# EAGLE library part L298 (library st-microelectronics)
DUAL FULL-BRIDGE DRIVER

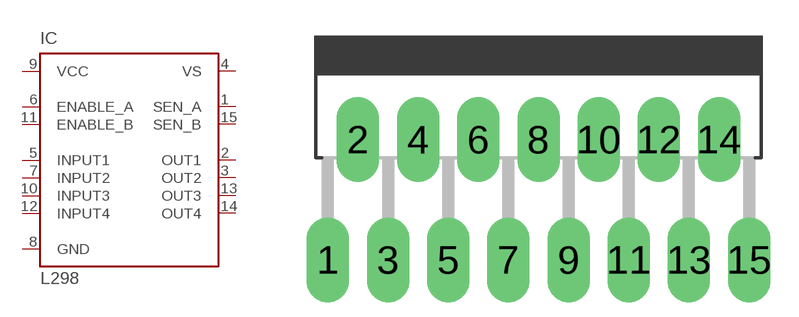
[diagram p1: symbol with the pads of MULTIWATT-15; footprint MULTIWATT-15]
Designator prefix IC

## L298 (MPN: L298N; OC_FARNELL: 1589425; OC_NEWARK: 32M1527)  [MULTIWATT-15]
1  SEN_A  in
2  OUT1  out
3  OUT2  out
4  VS  pwr
5  INPUT1  in
6  ENABLE_A  in
7  INPUT2  in
8  GND  pwr
9  VCC  pwr
10  INPUT3  in
11  ENABLE_B  in
12  INPUT4  in
13  OUT3  out
14  OUT4  out
15  SEN_B  in

## Footprint MULTIWATT-15 (pad centres in mm)
Multiwatt 15 lead
drill 1.2 long: 1 -8.89,-7.62; 2 -7.62,-2.54; 3 -6.35,-7.62; 4 -5.08,-2.54; 5 -3.81,-7.62; 6 -2.54,-2.54; 7 -1.27,-7.62; 8 0,-2.54; 9 1.27,-7.62; 10 2.54,-2.54; 11 3.81,-7.62; 12 5.08,-2.54; 13 6.35,-7.62; 14 7.62,-2.54; 15 8.89,-7.62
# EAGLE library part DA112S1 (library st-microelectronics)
DIODE ARRAY (ASD)

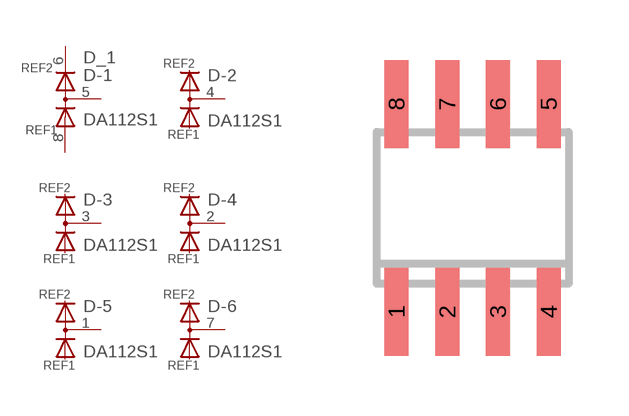
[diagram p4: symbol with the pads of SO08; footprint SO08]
Designator prefix D; gates _1=REF -1=D-1 -2=D-2-1 -3=D-2-1 -4=D-2-1 -5=D-2-1 -6=D-2-1

## DA112S1 (MF: Arrow Electronics; MPN: DA112S1; OC_FARNELL: 9802223; OC_NEWARK: 89K0514)  [SO08]
1  -5:K  pas
2  -4:K  pas
3  -3:K  pas
4  -2:K  pas
5  -1:K  pas
6  _1:REF2  pas
7  -6:K  pas
8  _1:REF1  pas

## Footprint SO08 (pad centres in mm)
SMALL OUTLINE INTEGRATED CIRCUIT body 3.9 mm/JEDEC MS-012AA
smd 0.6 x 2.2: 1 -1.905,-2.6; 2 -0.635,-2.6; 3 0.635,-2.6; 4 1.905,-2.6; 5 1.905,2.6; 6 0.635,2.6; 7 -0.635,2.6; 8 -1.905,2.6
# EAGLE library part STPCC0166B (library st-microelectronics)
MICROCONTROLLER

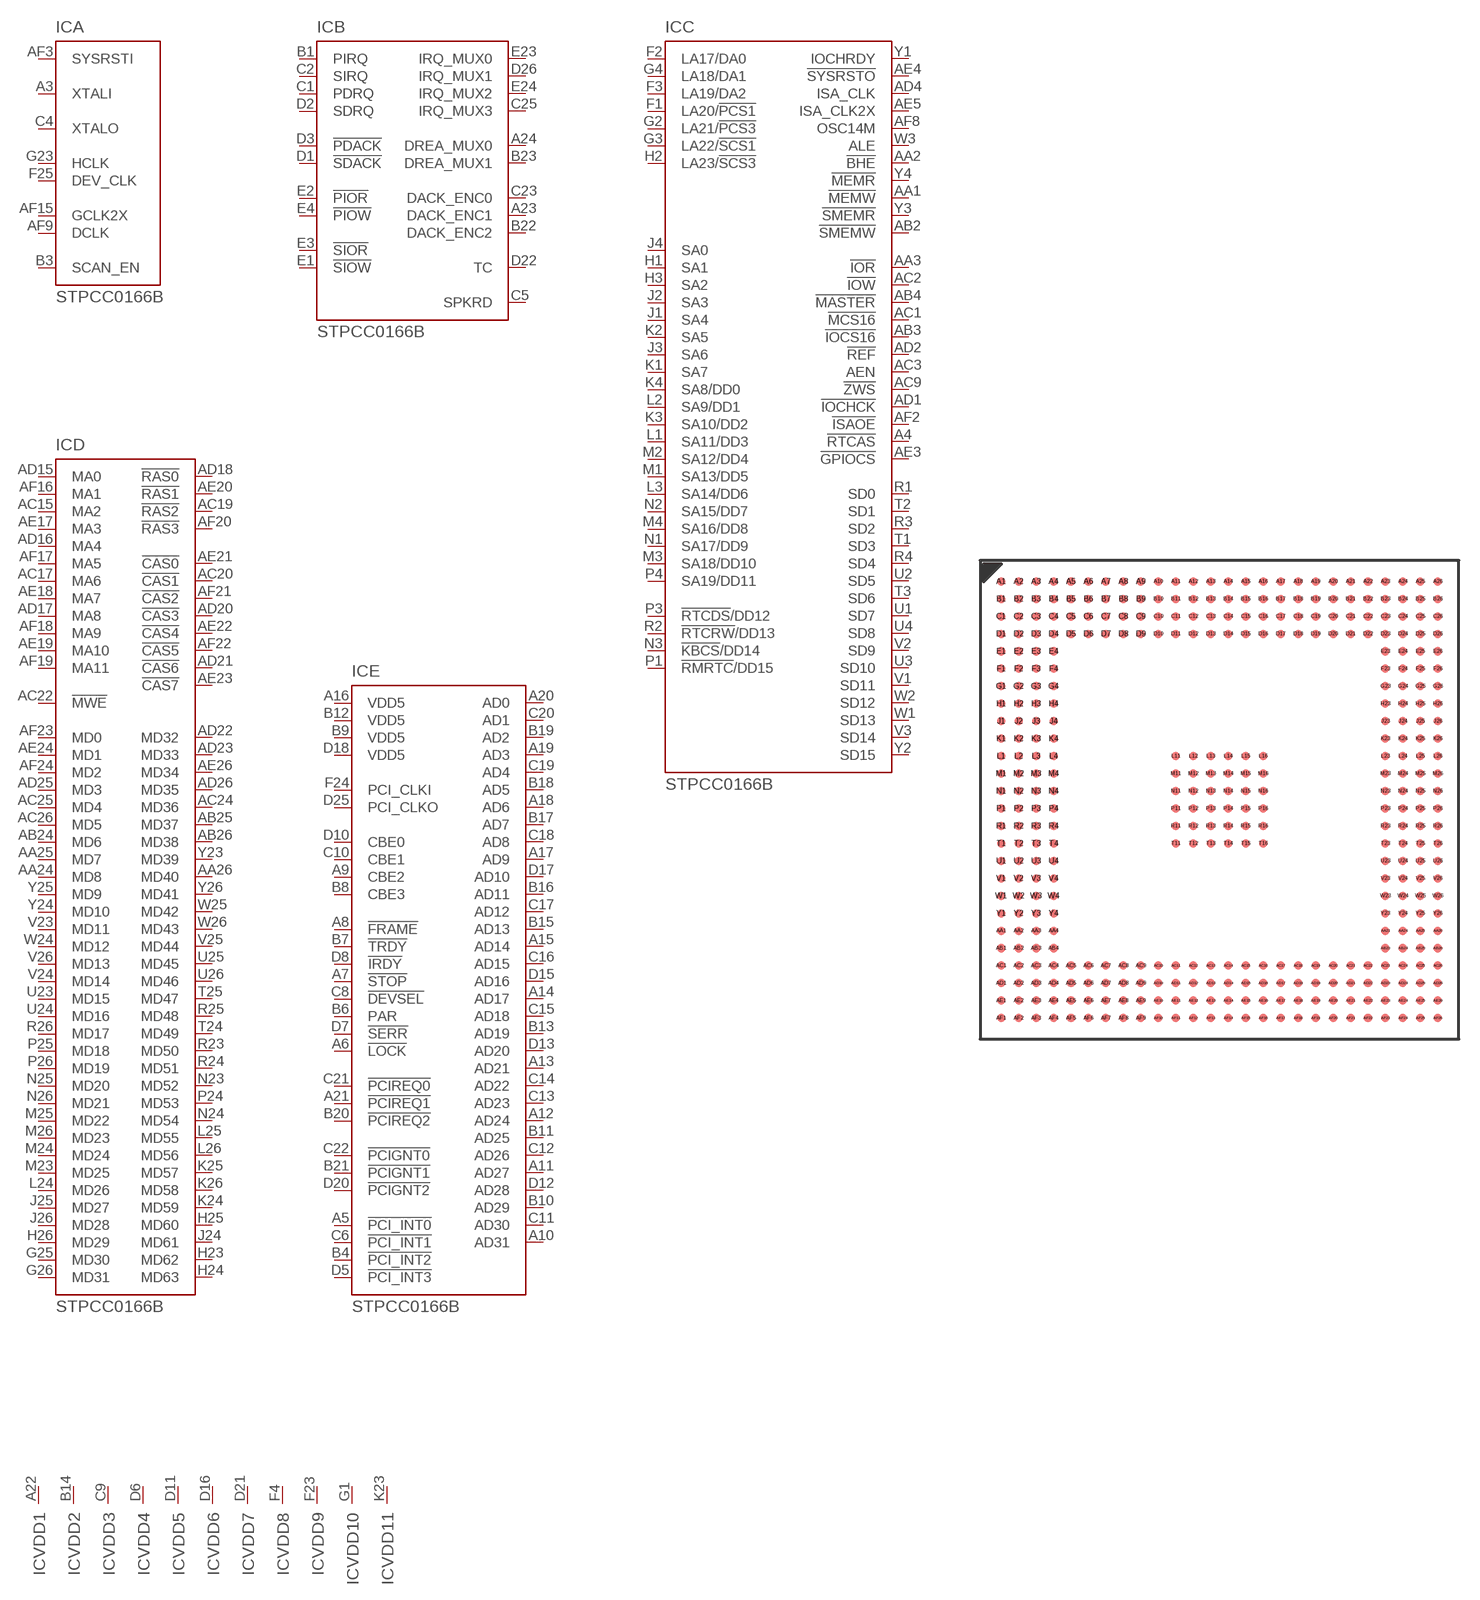
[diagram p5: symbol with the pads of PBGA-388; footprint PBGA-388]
Designator prefix IC; gates A=C0166BAS B=C0166IDE C=C0166ISA D=C0166MEM E=C0166PCI VDD1=VDD VDD2=VDD VDD3=VDD VDD4=VDD VDD5=VDD VDD6=VDD VDD7=VDD VDD8=VDD VDD9=VDD VDD10=VDD VDD11=VDD VDD12=VDD VDD13=VDD VDD14=VDD VDD15=VDD VDD16=VDD VDD17=VDD VDD18=VDD VDD19=VDD VDD20=VDD VDD21=VDD VDD22=VDD VDD23=VDD VDD24=VDD VSS1=VSS VSS2=VSS VSS3=VSS VSS4=VSS VSS5=VSS VSS6=VSS VSS7=VSS VSS8=VSS VSS9=VSS VSS10=VSS VSS11=VSS VSS12=VSS VSS13=VSS VSS14=VSS VSS15=VSS VSS16=VSS VSS17=VSS VSS18=VSS VSS19=VSS VSS20=VSS VSS21=VSS VSS22=VSS VSS23=VSS VSS24=VSS VDD25=VDD VDD26=VDD VSS25=VSS VSS26=VSS VSS27=VSS VSS28=VSS VSS29=VSS VSS30=VSS VSS31=VSS VSS32=VSS VSS33=VSS VSS34=VSS VSS35=VSS VSS36=VSS VSS37=VSS VSS38=VSS VSS39=VSS VSS40=VSS VSS41=VSS VSS42=VSS VSS43=VSS VSS44=VSS VSS45=VSS VSS46=VSS VSS47=VSS VSS48=VSS VSS49=VSS VSS50=VSS VSS51=VSS VSS52=VSS VSS53=VSS VSS54=VSS VSS55=VSS VSS56=VSS VSS57=VSS VSS58=VSS VSS59=VSS VSS60=VSS VSS61=VSS VSS62=VSS VSS63=VSS VSS64=VSS VSS65=VSS VSS66=VSS VSS67=VSS VSS68=VSS RESERV1=RESERVED RESERV2=RESERVED RESERV3=RESERVED RESERV4=RESERVED F=C0166MON VSS69=VSS

## STPCC0166B (MPN: STPCC5HEBC; OC_FARNELL: unknown; OC_NEWARK: 37M6674)  [PBGA-388]
A1  VSS1:VSS  pwr
A2  VSS69:VSS  pwr
A3  A:XTALI  in
A4  C:!RTCAS  out
A5  E:!PCI_INT0  in
A6  E:!LOCK  in
A7  E:!STOP
A8  E:!FRAME
A9  E:CBE2
A10  E:AD31
A11  E:AD27
A12  E:AD24
A13  E:AD21
A14  E:AD17
A15  E:AD14
A16  E:VDD5  pwr
A17  E:AD9
A18  E:AD6
A19  E:AD3
A20  E:AD0
A21  E:!PCIREQ1  in
A22  VDD1:VDD  pwr
A23  B:DACK_ENC1  out
A24  B:DREA_MUX0  in
A25  RESERV4:RESERVED  nc
A26  VSS2:VSS  pwr
AA1  C:!MEMW
AA2  C:!BHE
AA3  C:!IOR
AA4  VDD19:VDD  pwr
AA23  VDD20:VDD  pwr
AA24  D:MD8
AA25  D:MD7
AA26  D:MD40
AB1  VDD21:VDD  pwr
AB2  C:!SMEMW  out
AB3  C:!IOCS16  in
AB4  C:!MASTER  in
AB23  VDD22:VDD  pwr
AB24  D:MD6
AB25  D:MD37
AB26  D:MD38
AC1  C:!MCS16  in
AC2  C:!IOW
AC3  C:AEN  out
AC4  VSS55:VSS  pwr
AC5  F:HSYNC  out
AC6  VDD23:VDD  pwr
AC7  F:VDD_DAC1  in
AC8  VSS56:VSS  pwr
AC9  C:!ZWS  in
AC10  F:GREEN_TV  out
AC11  VDD24:VDD  pwr
AC12  F:VCLK  in
AC13  VSS57:VSS  pwr
AC14  F:VIN4  in
AC15  D:MA2
AC16  VDD25:VDD  pwr
AC17  D:MA6
AC18  VSS58:VSS  pwr
AC19  D:!RAS2  out
AC20  D:!CAS1  out
AC21  VDD26:VDD  pwr
AC22  D:!MWE
AC23  VSS59:VSS  pwr
AC24  D:MD36
AC25  D:MD4
AC26  D:MD5
AD1  C:!IOCHCK  in
AD2  C:!REF  out
AD3  VSS60:VSS  pwr
AD4  C:ISA_CLK  out
AD5  F:VSYNC  out
AD6  F:GREEN  out
AD7  F:VREF_DAC  in
AD8  F:IREF1_TV  in
AD9  F:ODD_EVEN  out
AD10  F:VREF2_TV  in
AD11  F:CVBS  out
AD12  F:VIN2  in
AD13  F:VIN6  in
AD14  F:VIN1  in
AD15  D:MA0
AD16  D:MA4
AD17  D:MA8
AD18  D:!RAS0  out
AD19  F:VDDGCKPLL  in
AD20  D:!CAS3  out
AD21  D:!CAS6  out
AD22  D:MD32
AD23  D:MD33
AD24  VSS61:VSS  pwr
AD25  D:MD3
AD26  D:MD35
AE1  VSS62:VSS  pwr
AE2  VSS63:VSS  pwr
AE3  C:!GPIOCS
AE4  C:!SYSRSTO  out
AE5  C:ISA_CLK2X  out
AE6  F:RED  out
AE7  F:VSS_DAC1  in
AE8  F:RSET  in
AE9  F:VREF1_TV  in
AE10  F:VCS  out
AE11  F:IREF2_TV  in
AE12  F:VSSA_TV  in
AE13  F:VIN0  in
AE14  F:VIN3  in
AE15  F:VIN7  in
AE16  VSS64:VSS  pwr
AE17  D:MA3
AE18  D:MA7
AE19  D:MA10
AE20  D:!RAS1  out
AE21  D:!CAS0  out
AE22  D:!CAS4  out
AE23  D:!CAS7  out
AE24  D:MD1
AE25  VSS65:VSS  pwr
AE26  D:MD34
AF1  VSS66:VSS  pwr
AF2  C:!ISAOE  out
AF3  A:SYSRSTI  in
AF4  F:VDD_DAC2  in
AF5  F:COMP  in
AF6  F:BLUE  out
AF7  F:VSS_DAC2  in
AF8  C:OSC14M  out
AF9  A:DCLK
AF10  F:RED_TV  out
AF11  F:BLUE_TV  out
AF12  F:VDDA_TV  in
AF13  F:VDDDCKPLL  in
AF14  F:VIN5  in
AF15  A:GCLK2X
AF16  D:MA1
AF17  D:MA5
AF18  D:MA9
AF19  D:MA11
AF20  D:!RAS3  out
AF21  D:!CAS2  out
AF22  D:!CAS5  out
AF23  D:MD0
AF24  D:MD2
AF25  VSS67:VSS  pwr
AF26  VSS68:VSS  pwr
B1  B:PIRQ  in
B2  VSS3:VSS  pwr
B3  A:SCAN_EN  in
B4  E:!PCI_INT2  in
B5  F:SLC/DDC1
B6  E:PAR
B7  E:!TRDY
B8  E:CBE3
B9  E:VDD5  pwr
B10  E:AD29
B11  E:AD25
B12  E:VDD5  pwr
B13  E:AD19
B14  VDD2:VDD  pwr
B15  E:AD13
B16  E:AD11
B17  E:AD7
B18  E:AD5
B19  E:AD2
B20  E:!PCIREQ2  in
B21  E:!PCIGNT1  out
B22  B:DACK_ENC2  out
B23  B:DREA_MUX1  in
B24  RESERV3:RESERVED  nc
B25  VSS4:VSS  pwr
B26  VSS5:VSS  pwr
C1  B:PDRQ  in
C2  B:SIRQ  in
C3  VSS6:VSS  pwr
C4  A:XTALO
C5  B:SPKRD  out
C6  E:!PCI_INT1  in
C7  F:SDA/DDC0
C8  E:!DEVSEL
C9  VDD3:VDD  pwr
C10  E:CBE1
C11  E:AD30
C12  E:AD26
C13  E:AD23
C14  E:AD22
C15  E:AD18
C16  E:AD15
C17  E:AD12
C18  E:AD8
C19  E:AD4
C20  E:AD1
C21  E:!PCIREQ0  in
C22  E:!PCIGNT0  out
C23  B:DACK_ENC0  out
C24  VSS7:VSS  pwr
C25  B:IRQ_MUX3  in
C26  RESERV1:RESERVED  nc
D1  B:!SDACK  out
D2  B:SDRQ  in
D3  B:!PDACK  out
D4  VSS8:VSS  pwr
D5  E:!PCI_INT3  in
D6  VDD4:VDD  pwr
D7  E:!SERR  out
D8  E:!IRDY
D9  VSS9:VSS  pwr
D10  E:CBE0
D11  VDD5:VDD  pwr
D12  E:AD28
D13  E:AD20
D14  VSS10:VSS  pwr
D15  E:AD16
D16  VDD6:VDD  pwr
D17  E:AD10
D18  E:VDD5  pwr
D19  VSS11:VSS  pwr
D20  E:!PCIGNT2  out
D21  VDD7:VDD  pwr
D22  B:TC  out
D23  VSS12:VSS  pwr
D24  RESERV2:RESERVED  nc
D25  E:PCI_CLKO  out
D26  B:IRQ_MUX1  in
E1  B:!SIOW  out
E2  B:!PIOR
E3  B:!SIOR
E4  B:!PIOW  out
E23  B:IRQ_MUX0  in
E24  B:IRQ_MUX2  in
E25  F:VSS_DLL1  in
E26  F:VSS_DLL2  in
F1  C:LA20/!PCS1
F2  C:LA17/DA0  out
F3  C:LA19/DA2  out
F4  VDD8:VDD  pwr
F23  VDD9:VDD  pwr
F24  E:PCI_CLKI  in
F25  A:DEV_CLK  out
F26  F:VDDHCKPLL  in
G1  VDD10:VDD  pwr
G2  C:LA21/!PCS3
G3  C:LA22/!SCS1
G4  C:LA18/DA1  out
G23  A:HCLK  out
G24  F:VDDDEVPLL  in
G25  D:MD30
G26  D:MD31
H1  C:SA1
H2  C:LA23/!SCS3
H3  C:SA2
H4  VSS13:VSS  pwr
H23  D:MD62
H24  D:MD63
H25  D:MD60
H26  D:MD29
J1  C:SA4
J2  C:SA3
J3  C:SA6
J4  C:SA0
J23  VSS14:VSS  pwr
J24  D:MD61
J25  D:MD27
J26  D:MD28
K1  C:SA7
K2  C:SA5
K3  C:SA10/DD2
K4  C:SA8/DD0
K23  VDD11:VDD  pwr
K24  D:MD59
K25  D:MD57
K26  D:MD58
L1  C:SA11/DD3
L2  C:SA9/DD1
L3  C:SA14/DD6
L4  VDD12:VDD  pwr
L11  VSS15:VSS  pwr
L12  VSS16:VSS  pwr
L13  VSS17:VSS  pwr
L14  VSS18:VSS  pwr
L15  VSS19:VSS  pwr
L16  VSS20:VSS  pwr
L23  VDD13:VDD  pwr
L24  D:MD26
L25  D:MD55
L26  D:MD56
M1  C:SA13/DD5
M2  C:SA12/DD4
M3  C:SA18/DD10
M4  C:SA16/DD8
M11  VSS21:VSS  pwr
M12  VSS22:VSS  pwr
M13  VSS23:VSS  pwr
M14  VSS24:VSS  pwr
M15  VSS25:VSS  pwr
M16  VSS26:VSS  pwr
M23  D:MD25
M24  D:MD24
M25  D:MD22
M26  D:MD23
N1  C:SA17/DD9
N2  C:SA15/DD7
N3  C:!KBCS!/DD14
N4  VSS27:VSS  pwr
N11  VSS28:VSS  pwr
N12  VSS29:VSS  pwr
N13  VSS30:VSS  pwr
N14  VSS31:VSS  pwr
N15  VSS32:VSS  pwr
N16  VSS33:VSS  pwr
N23  D:MD52
N24  D:MD54
N25  D:MD20
N26  D:MD21
P1  C:!RMRTC!/DD15
P2  VDD14:VDD  pwr
P3  C:!RTCDS!/DD12
P4  C:SA19/DD11
P11  VSS34:VSS  pwr
P12  VSS35:VSS  pwr
P13  VSS36:VSS  pwr
P14  VSS37:VSS  pwr
P15  VSS38:VSS  pwr
P16  VSS39:VSS  pwr
P23  VSS40:VSS  pwr
P24  D:MD53
P25  D:MD18
P26  D:MD19
R1  C:SD0
R2  C:!RTCRW!/DD13
R3  C:SD2
R4  C:SD4
R11  VSS41:VSS  pwr
R12  VSS42:VSS  pwr
R13  VSS43:VSS  pwr
R14  VSS44:VSS  pwr
R15  VSS45:VSS  pwr
R16  VSS46:VSS  pwr
R23  D:MD50
R24  D:MD51
R25  D:MD48
R26  D:MD17
T1  C:SD3
T2  C:SD1
T3  C:SD6
T4  VDD15:VDD  pwr
T11  VSS47:VSS  pwr
T12  VSS48:VSS  pwr
T13  VSS49:VSS  pwr
T14  VSS50:VSS  pwr
T15  VSS51:VSS  pwr
T16  VSS52:VSS  pwr
T23  VDD16:VDD  pwr
T24  D:MD49
T25  D:MD47
T26  VDD17:VDD  pwr
U1  C:SD7
U2  C:SD5
U3  C:SD10
U4  C:SD8
U23  D:MD15
U24  D:MD16
U25  D:MD45
U26  D:MD46
V1  C:SD11
V2  C:SD9
V3  C:SD14
V4  VSS53:VSS  pwr
V23  D:MD11
V24  D:MD14
V25  D:MD44
V26  D:MD13
W1  C:SD13
W2  C:SD12
W3  C:ALE  out
W4  VDD18:VDD  pwr
W23  VSS54:VSS  pwr
W24  D:MD12
W25  D:MD42
W26  D:MD43
Y1  C:IOCHRDY
Y2  C:SD15
Y3  C:!SMEMR  out
Y4  C:!MEMR
Y23  D:MD39
Y24  D:MD10
Y25  D:MD9
Y26  D:MD41

## Footprint PBGA-388 (pad centres in mm)
Plastic Ball Grid Array
smd 0.635 x 0.635: A1 -15.875,15.875; A2 -14.605,15.875; A3 -13.335,15.875; A4 -12.065,15.875; A5 -10.795,15.875; A6 -9.525,15.875; A7 -8.255,15.875; A8 -6.985,15.875; A9 -5.715,15.875; A10 -4.445,15.875; A11 -3.175,15.875; A12 -1.905,15.875; A13 -0.635,15.875; A14 0.635,15.875; A15 1.905,15.875; A16 3.175,15.875; A17 4.445,15.875; A18 5.715,15.875; A19 6.985,15.875; A20 8.255,15.875; A21 9.525,15.875; A22 10.795,15.875; A23 12.065,15.875; A24 13.335,15.875; A25 14.605,15.875; A26 15.875,15.875; AA1 -15.875,-9.525; AA2 -14.605,-9.525; AA3 -13.335,-9.525; AA4 -12.065,-9.525; AA23 12.065,-9.525; AA24 13.335,-9.525; AA25 14.605,-9.525; AA26 15.875,-9.525; AB1 -15.875,-10.795; AB2 -14.605,-10.795; AB3 -13.335,-10.795; AB4 -12.065,-10.795; AB23 12.065,-10.795; AB24 13.335,-10.795; AB25 14.605,-10.795; AB26 15.875,-10.795; AC1 -15.875,-12.065; AC2 -14.605,-12.065; AC3 -13.335,-12.065; AC4 -12.065,-12.065; AC5 -10.795,-12.065; AC6 -9.525,-12.065; AC7 -8.255,-12.065; AC8 -6.985,-12.065; AC9 -5.715,-12.065; AC10 -4.445,-12.065; AC11 -3.175,-12.065; AC12 -1.905,-12.065; AC13 -0.635,-12.065; AC14 0.635,-12.065; AC15 1.905,-12.065; AC16 3.175,-12.065; AC17 4.445,-12.065; AC18 5.715,-12.065; AC19 6.985,-12.065; AC20 8.255,-12.065; AC21 9.525,-12.065; AC22 10.795,-12.065; AC23 12.065,-12.065; AC24 13.335,-12.065; AC25 14.605,-12.065; AC26 15.875,-12.065; AD1 -15.875,-13.335; AD2 -14.605,-13.335; AD3 -13.335,-13.335; AD4 -12.065,-13.335; AD5 -10.795,-13.335; AD6 -9.525,-13.335; AD7 -8.255,-13.335; AD8 -6.985,-13.335; AD9 -5.715,-13.335; AD10 -4.445,-13.335; AD11 -3.175,-13.335; AD12 -1.905,-13.335; AD13 -0.635,-13.335; AD14 0.635,-13.335; AD15 1.905,-13.335; AD16 3.175,-13.335; AD17 4.445,-13.335; AD18 5.715,-13.335; AD19 6.985,-13.335; AD20 8.255,-13.335; AD21 9.525,-13.335; AD22 10.795,-13.335; AD23 12.065,-13.335; AD24 13.335,-13.335; AD25 14.605,-13.335; AD26 15.875,-13.335; AE1 -15.875,-14.605; AE2 -14.605,-14.605; AE3 -13.335,-14.605; AE4 -12.065,-14.605; AE5 -10.795,-14.605; AE6 -9.525,-14.605; AE7 -8.255,-14.605; AE8 -6.985,-14.605; AE9 -5.715,-14.605; AE10 -4.445,-14.605; AE11 -3.175,-14.605; AE12 -1.905,-14.605; AE13 -0.635,-14.605; AE14 0.635,-14.605; AE15 1.905,-14.605; AE16 3.175,-14.605; AE17 4.445,-14.605; AE18 5.715,-14.605; AE19 6.985,-14.605; AE20 8.255,-14.605; AE21 9.525,-14.605; AE22 10.795,-14.605; AE23 12.065,-14.605; AE24 13.335,-14.605; AE25 14.605,-14.605; AE26 15.875,-14.605; AF1 -15.875,-15.875; AF2 -14.605,-15.875; AF3 -13.335,-15.875; AF4 -12.065,-15.875; AF5 -10.795,-15.875; AF6 -9.525,-15.875; AF7 -8.255,-15.875; AF8 -6.985,-15.875; AF9 -5.715,-15.875; AF10 -4.445,-15.875; AF11 -3.175,-15.875; AF12 -1.905,-15.875; AF13 -0.635,-15.875; AF14 0.635,-15.875; AF15 1.905,-15.875; AF16 3.175,-15.875; AF17 4.445,-15.875; AF18 5.715,-15.875; AF19 6.985,-15.875; AF20 8.255,-15.875; AF21 9.525,-15.875; AF22 10.795,-15.875; AF23 12.065,-15.875; AF24 13.335,-15.875; AF25 14.605,-15.875; AF26 15.875,-15.875; B1 -15.875,14.605; B2 -14.605,14.605; B3 -13.335,14.605; B4 -12.065,14.605; B5 -10.795,14.605; B6 -9.525,14.605; B7 -8.255,14.605; B8 -6.985,14.605; B9 -5.715,14.605; B10 -4.445,14.605; B11 -3.175,14.605; B12 -1.905,14.605; B13 -0.635,14.605; B14 0.635,14.605; B15 1.905,14.605; B16 3.175,14.605; B17 4.445,14.605; B18 5.715,14.605; B19 6.985,14.605; B20 8.255,14.605; B21 9.525,14.605; B22 10.795,14.605; B23 12.065,14.605; B24 13.335,14.605; B25 14.605,14.605; B26 15.875,14.605; C1 -15.875,13.335; C2 -14.605,13.335; C3 -13.335,13.335; C4 -12.065,13.335; C5 -10.795,13.335; C6 -9.525,13.335; C7 -8.255,13.335; C8 -6.985,13.335; C9 -5.715,13.335; C10 -4.445,13.335; C11 -3.175,13.335; C12 -1.905,13.335; C13 -0.635,13.335; C14 0.635,13.335; C15 1.905,13.335; C16 3.175,13.335; C17 4.445,13.335; C18 5.715,13.335; C19 6.985,13.335; C20 8.255,13.335; C21 9.525,13.335; C22 10.795,13.335; C23 12.065,13.335; C24 13.335,13.335; C25 14.605,13.335; C26 15.875,13.335; D1 -15.875,12.065; D2 -14.605,12.065; D3 -13.335,12.065; D4 -12.065,12.065; D5 -10.795,12.065; D6 -9.525,12.065; D7 -8.255,12.065; D8 -6.985,12.065; D9 -5.715,12.065; D10 -4.445,12.065; D11 -3.175,12.065; D12 -1.905,12.065; D13 -0.635,12.065; D14 0.635,12.065; D15 1.905,12.065; D16 3.175,12.065; D17 4.445,12.065; D18 5.715,12.065; D19 6.985,12.065; D20 8.255,12.065; D21 9.525,12.065; D22 10.795,12.065; D23 12.065,12.065; D24 13.335,12.065; D25 14.605,12.065; D26 15.875,12.065; E1 -15.875,10.795; E2 -14.605,10.795; E3 -13.335,10.795; E4 -12.065,10.795; E23 12.065,10.795; E24 13.335,10.795; E25 14.605,10.795; E26 15.875,10.795; F1 -15.875,9.525; F2 -14.605,9.525; F3 -13.335,9.525; F4 -12.065,9.525; F23 12.065,9.525; F24 13.335,9.525; F25 14.605,9.525; F26 15.875,9.525; G1 -15.875,8.255; G2 -14.605,8.255; G3 -13.335,8.255; G4 -12.065,8.255; G23 12.065,8.255; G24 13.335,8.255; G25 14.605,8.255; G26 15.875,8.255; H1 -15.875,6.985; H2 -14.605,6.985; H3 -13.335,6.985; H4 -12.065,6.985; H23 12.065,6.985; H24 13.335,6.985; H25 14.605,6.985; H26 15.875,6.985; J1 -15.875,5.715; J2 -14.605,5.715; J3 -13.335,5.715; J4 -12.065,5.715; J23 12.065,5.715; J24 13.335,5.715; J25 14.605,5.715; J26 15.875,5.715; K1 -15.875,4.445; K2 -14.605,4.445; K3 -13.335,4.445; K4 -12.065,4.445; K23 12.065,4.445; K24 13.335,4.445; K25 14.605,4.445; K26 15.875,4.445; L1 -15.875,3.175; L2 -14.605,3.175; L3 -13.335,3.175; L4 -12.065,3.175; L11 -3.175,3.175; L12 -1.905,3.175; L13 -0.635,3.175; L14 0.635,3.175; L15 1.905,3.175; L16 3.175,3.175; L23 12.065,3.175; L24 13.335,3.175; L25 14.605,3.175; L26 15.875,3.175; M1 -15.875,1.905; M2 -14.605,1.905; M3 -13.335,1.905; M4 -12.065,1.905; M11 -3.175,1.905; M12 -1.905,1.905; M13 -0.635,1.905; M14 0.635,1.905; M15 1.905,1.905; M16 3.175,1.905; M23 12.065,1.905; M24 13.335,1.905; M25 14.605,1.905; M26 15.875,1.905; N1 -15.875,0.635; N2 -14.605,0.635; N3 -13.335,0.635; N4 -12.065,0.635; N11 -3.175,0.635; N12 -1.905,0.635; N13 -0.635,0.635; N14 0.635,0.635; N15 1.905,0.635; N16 3.175,0.635; N23 12.065,0.635; N24 13.335,0.635; N25 14.605,0.635; N26 15.875,0.635; P1 -15.875,-0.635; P2 -14.605,-0.635; P3 -13.335,-0.635; P4 -12.065,-0.635; P11 -3.175,-0.635; P12 -1.905,-0.635; P13 -0.635,-0.635; P14 0.635,-0.635; P15 1.905,-0.635; P16 3.175,-0.635; P23 12.065,-0.635; P24 13.335,-0.635; P25 14.605,-0.635; P26 15.875,-0.635; R1 -15.875,-1.905; R2 -14.605,-1.905; R3 -13.335,-1.905; R4 -12.065,-1.905; R11 -3.175,-1.905; R12 -1.905,-1.905; R13 -0.635,-1.905; R14 0.635,-1.905; R15 1.905,-1.905; R16 3.175,-1.905; R23 12.065,-1.905; R24 13.335,-1.905; R25 14.605,-1.905; R26 15.875,-1.905; T1 -15.875,-3.175; T2 -14.605,-3.175; T3 -13.335,-3.175; T4 -12.065,-3.175; T11 -3.175,-3.175; T12 -1.905,-3.175; T13 -0.635,-3.175; T14 0.635,-3.175; T15 1.905,-3.175; T16 3.175,-3.175; T23 12.065,-3.175; T24 13.335,-3.175; T25 14.605,-3.175; T26 15.875,-3.175; U1 -15.875,-4.445; U2 -14.605,-4.445; U3 -13.335,-4.445; U4 -12.065,-4.445; U23 12.065,-4.445; U24 13.335,-4.445; U25 14.605,-4.445; U26 15.875,-4.445; V1 -15.875,-5.715; V2 -14.605,-5.715; V3 -13.335,-5.715; V4 -12.065,-5.715; V23 12.065,-5.715; V24 13.335,-5.715; V25 14.605,-5.715; V26 15.875,-5.715; W1 -15.875,-6.985; W2 -14.605,-6.985; W3 -13.335,-6.985; W4 -12.065,-6.985; W23 12.065,-6.985; W24 13.335,-6.985; W25 14.605,-6.985; W26 15.875,-6.985; Y1 -15.875,-8.255; Y2 -14.605,-8.255; Y3 -13.335,-8.255; Y4 -12.065,-8.255; Y23 12.065,-8.255; Y24 13.335,-8.255; Y25 14.605,-8.255; Y26 15.875,-8.255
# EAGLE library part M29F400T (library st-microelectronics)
FLASH MEMORY 512 KB x 8 or 256 KB x 16, boot block

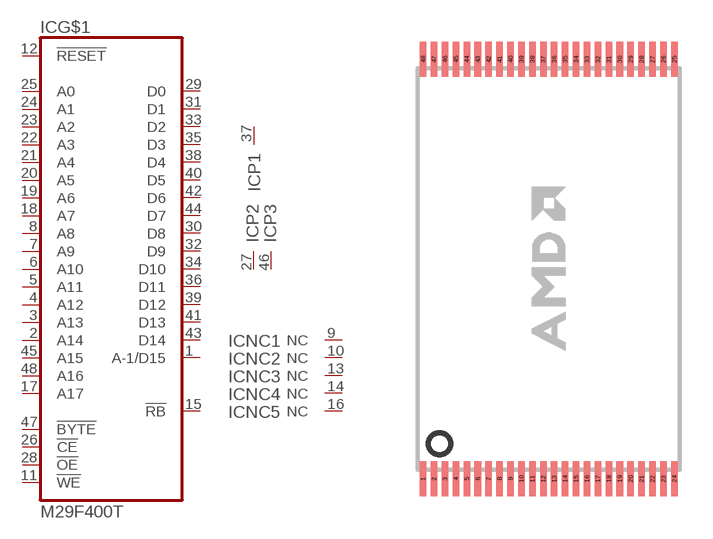
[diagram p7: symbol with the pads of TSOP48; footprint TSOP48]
Designator prefix IC; gates G$1=M29F400 P1=VCC P2=GND P3=GND NC1=NC NC2=NC NC3=NC NC4=NC NC5=NC

## M29F400T (MPN: MBM29F400TC-70PFTN-SFLE1; OC_FARNELL: 1201518; OC_NEWARK: 89M1908)  [TSOP48]
1  G$1:A-1/D15  hiz
2  G$1:A14  in
3  G$1:A13  in
4  G$1:A12  in
5  G$1:A11  in
6  G$1:A10  in
7  G$1:A9  in
8  G$1:A8  in
9  NC1:NC  nc
10  NC2:NC  nc
11  G$1:!WE  in
12  G$1:!RESET  in
13  NC3:NC  nc
14  NC4:NC  nc
15  G$1:!RB  out
16  NC5:NC  nc
17  G$1:A17  in
18  G$1:A7  in
19  G$1:A6  in
20  G$1:A5  in
21  G$1:A4  in
22  G$1:A3  in
23  G$1:A2  in
24  G$1:A1  in
25  G$1:A0  in
26  G$1:!CE  in
27  P2:GND  pwr
28  G$1:!OE  in
29  G$1:D0  hiz
30  G$1:D8  hiz
31  G$1:D1  hiz
32  G$1:D9  hiz
33  G$1:D2  hiz
34  G$1:D10  hiz
35  G$1:D3  hiz
36  G$1:D11  hiz
37  P1:VCC  pwr
38  G$1:D4  hiz
39  G$1:D12  hiz
40  G$1:D5  hiz
41  G$1:D13  hiz
42  G$1:D6  hiz
43  G$1:D14  hiz
44  G$1:D7  hiz
45  G$1:A15  in
46  P3:GND  pwr
47  G$1:!BYTE  in
48  G$1:A16  in

## Footprint TSOP48 (pad centres in mm)
Thin Small Outline Plastic Package
smd 0.3 x 1.6: 1 -5.75,-9.6; 2 -5.25,-9.6; 3 -4.75,-9.6; 4 -4.25,-9.6; 5 -3.75,-9.6; 6 -3.25,-9.6; 7 -2.75,-9.6; 8 -2.25,-9.6; 9 -1.75,-9.6; 10 -1.25,-9.6; 11 -0.75,-9.6; 12 -0.25,-9.6; 13 0.25,-9.6; 14 0.75,-9.6; 15 1.25,-9.6; 16 1.75,-9.6; 17 2.25,-9.6; 18 2.75,-9.6; 19 3.25,-9.6; 20 3.75,-9.6; 21 4.25,-9.6; 22 4.75,-9.6; 23 5.25,-9.6; 24 5.75,-9.6; 25 5.75,9.6; 26 5.25,9.6; 27 4.75,9.6; 28 4.25,9.6; 29 3.75,9.6; 30 3.25,9.6; 31 2.75,9.6; 32 2.25,9.6; 33 1.75,9.6; 34 1.25,9.6; 35 0.75,9.6; 36 0.25,9.6; 37 -0.25,9.6; 38 -0.75,9.6; 39 -1.25,9.6; 40 -1.75,9.6; 41 -2.25,9.6; 42 -2.75,9.6; 43 -3.25,9.6; 44 -3.75,9.6; 45 -4.25,9.6; 46 -4.75,9.6; 47 -5.25,9.6; 48 -5.75,9.6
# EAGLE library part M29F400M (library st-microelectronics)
FLASH MEMORY 512 KB x 8 or 256 KB x 16, boot block

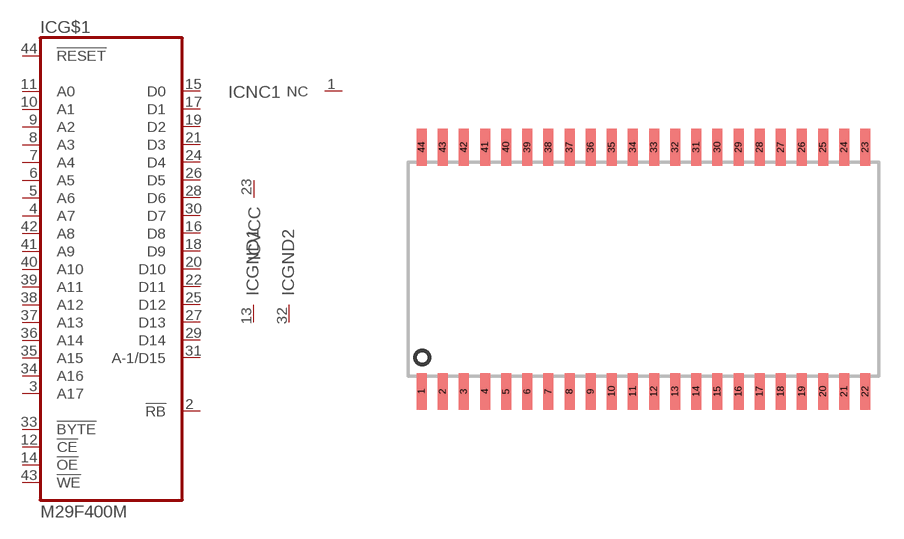
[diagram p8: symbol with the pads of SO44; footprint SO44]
Designator prefix IC; gates G$1=M29F400 NC1=NC VCC=VCC GND1=GND GND2=GND

## M29F400M (MF: SPANSION LLC; MPN: AM29F400BB-90SF; OC_FARNELL: 1607577; OC_NEWARK: 58K5516)  [SO44]
1  NC1:NC  nc
2  G$1:!RB  out
3  G$1:A17  in
4  G$1:A7  in
5  G$1:A6  in
6  G$1:A5  in
7  G$1:A4  in
8  G$1:A3  in
9  G$1:A2  in
10  G$1:A1  in
11  G$1:A0  in
12  G$1:!CE  in
13  GND1:GND  pwr
14  G$1:!OE  in
15  G$1:D0  hiz
16  G$1:D8  hiz
17  G$1:D1  hiz
18  G$1:D9  hiz
19  G$1:D2  hiz
20  G$1:D10  hiz
21  G$1:D3  hiz
22  G$1:D11  hiz
23  VCC:VCC  pwr
24  G$1:D4  hiz
25  G$1:D12  hiz
26  G$1:D5  hiz
27  G$1:D13  hiz
28  G$1:D6  hiz
29  G$1:D14  hiz
30  G$1:D7  hiz
31  G$1:A-1/D15  hiz
32  GND2:GND  pwr
33  G$1:!BYTE  in
34  G$1:A16  in
35  G$1:A15  in
36  G$1:A14  in
37  G$1:A13  in
38  G$1:A12  in
39  G$1:A11  in
40  G$1:A10  in
41  G$1:A9  in
42  G$1:A8  in
43  G$1:!WE  in
44  G$1:!RESET  in

## Footprint SO44 (pad centres in mm)
Small Outline Package
smd 0.6 x 2.2: 1 -13.335,-7.34; 2 -12.065,-7.34; 3 -10.795,-7.34; 4 -9.525,-7.34; 5 -8.255,-7.34; 6 -6.985,-7.34; 7 -5.715,-7.34; 8 -4.445,-7.34; 9 -3.175,-7.34; 10 -1.905,-7.34; 11 -0.635,-7.34; 12 0.635,-7.34; 13 1.905,-7.34; 14 3.175,-7.34; 15 4.445,-7.34; 16 5.715,-7.34; 17 6.985,-7.34; 18 8.255,-7.34; 19 9.525,-7.34; 20 10.795,-7.34; 21 12.065,-7.34; 22 13.335,-7.34; 23 13.335,7.34; 24 12.065,7.34; 25 10.795,7.34; 26 9.525,7.34; 27 8.255,7.34; 28 6.985,7.34; 29 5.715,7.34; 30 4.445,7.34; 31 3.175,7.34; 32 1.905,7.34; 33 0.635,7.34; 34 -0.635,7.34; 35 -1.905,7.34; 36 -3.175,7.34; 37 -4.445,7.34; 38 -5.715,7.34; 39 -6.985,7.34; 40 -8.255,7.34; 41 -9.525,7.34; 42 -10.795,7.34; 43 -12.065,7.34; 44 -13.335,7.34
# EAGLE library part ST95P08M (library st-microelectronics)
Serial EEPROM SPI bus, 1 K x 8

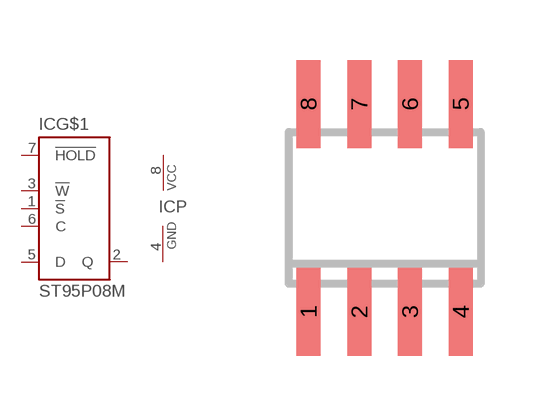
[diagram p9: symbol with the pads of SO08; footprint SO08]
Designator prefix IC; gates G$1=ST95P08 P=PWRN

## ST95P08M (OC_FARNELL: unknown; OC_NEWARK: unknown)  [SO08]
1  G$1:!S  in
2  G$1:Q  hiz
3  G$1:!W  in
4  P:GND  pwr
5  G$1:D  in
6  G$1:C  in
7  G$1:!HOLD  in
8  P:VCC  pwr

## Footprint SO08 (pad centres in mm)
SMALL OUTLINE INTEGRATED CIRCUIT body 3.9 mm/JEDEC MS-012AA
smd 0.6 x 2.2: 1 -1.905,-2.6; 2 -0.635,-2.6; 3 0.635,-2.6; 4 1.905,-2.6; 5 1.905,2.6; 6 0.635,2.6; 7 -0.635,2.6; 8 -1.905,2.6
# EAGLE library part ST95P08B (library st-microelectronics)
Serial EEPROM SPI bus, 1 K x 8

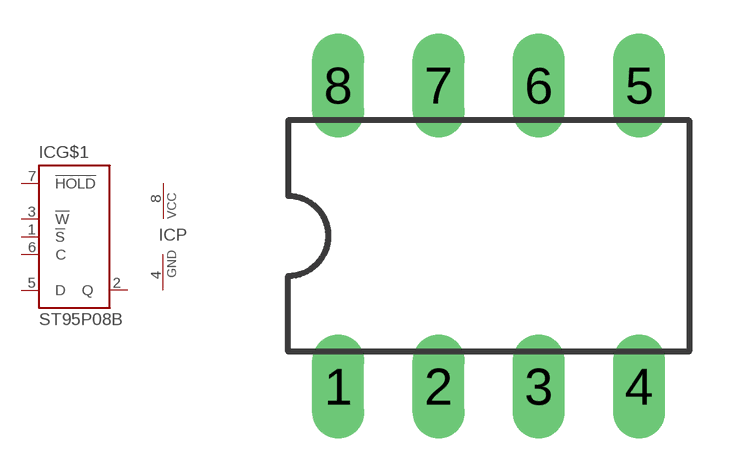
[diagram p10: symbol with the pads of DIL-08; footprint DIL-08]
Designator prefix IC; gates G$1=ST95P08 P=PWRN

## ST95P08B (OC_FARNELL: unknown; OC_NEWARK: unknown)  [DIL-08]
1  G$1:!S  in
2  G$1:Q  hiz
3  G$1:!W  in
4  P:GND  pwr
5  G$1:D  in
6  G$1:C  in
7  G$1:!HOLD  in
8  P:VCC  pwr

## Footprint DIL-08 (pad centres in mm)
Dual In Line Package
drill 0.813 long: 1 -3.81,-3.81; 2 -1.27,-3.81; 3 1.27,-3.81; 4 3.81,-3.81; 5 3.81,3.81; 6 1.27,3.81; 7 -1.27,3.81; 8 -3.81,3.81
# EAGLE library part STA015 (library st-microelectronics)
MP3 AUDIO DECODER with ADPCM capability

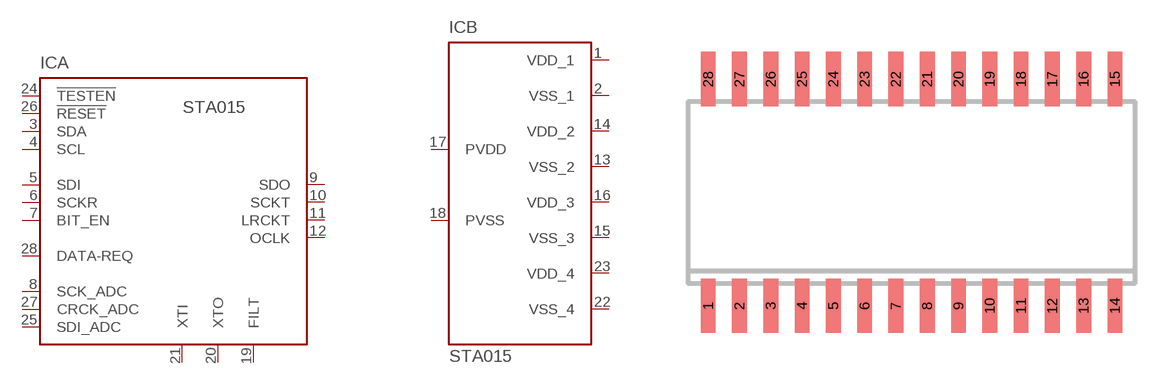
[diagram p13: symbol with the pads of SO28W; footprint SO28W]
Designator prefix IC; gates A=STA015S B=STA015PW

## STA015 (MPN: STA015$; OC_FARNELL: unknown; OC_NEWARK: 37M6100)  [SO28W]
1  B:VDD_1  pwr
2  B:VSS_1  pwr
3  A:SDA
4  A:SCL  in
5  A:SDI  in
6  A:SCKR  in
7  A:BIT_EN  in
8  A:SCK_ADC  in
9  A:SDO  out
10  A:SCKT  out
11  A:LRCKT  out
12  A:OCLK
13  B:VSS_2  pwr
14  B:VDD_2  pwr
15  B:VSS_3  pwr
16  B:VDD_3  pwr
17  B:PVDD  pwr
18  B:PVSS  pwr
19  A:FILT  out
20  A:XTO  out
21  A:XTI  in
22  B:VSS_4  pwr
23  B:VDD_4  pwr
24  A:!TESTEN  in
25  A:SDI_ADC  in
26  A:!RESET  in
27  A:CRCK_ADC  in
28  A:DATA-REQ  out

## Footprint SO28W (pad centres in mm)
SMALL OUTLINE INTEGRATED CIRCUIT wide body 7.5 mm/JEDEC MO-119AB
smd 0.6 x 2.2: 1 -8.255,-4.6; 2 -6.985,-4.6; 3 -5.715,-4.6; 4 -4.445,-4.6; 5 -3.175,-4.6; 6 -1.905,-4.6; 7 -0.635,-4.6; 8 0.635,-4.6; 9 1.905,-4.6; 10 3.175,-4.6; 11 4.445,-4.6; 12 5.715,-4.6; 13 6.985,-4.6; 14 8.255,-4.6; 15 8.255,4.6; 16 6.985,4.6; 17 5.715,4.6; 18 4.445,4.6; 19 3.175,4.6; 20 1.905,4.6; 21 0.635,4.6; 22 -0.635,4.6; 23 -1.905,4.6; 24 -3.175,4.6; 25 -4.445,4.6; 26 -5.715,4.6; 27 -6.985,4.6; 28 -8.255,4.6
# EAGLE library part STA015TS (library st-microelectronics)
MP3 AUDIO DECODER with ADPCM capability

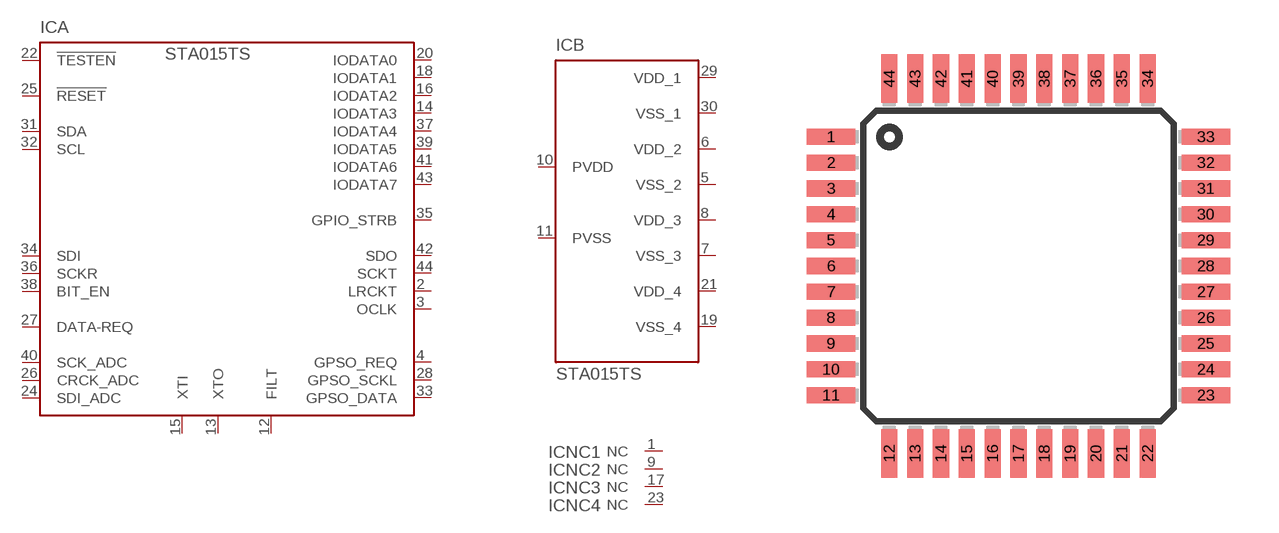
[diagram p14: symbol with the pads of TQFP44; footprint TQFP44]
Designator prefix IC; gates A=STA015TS B=STA015PW NC1=NC NC2=NC NC3=NC NC4=NC

## STA015TS (MPN: STA015T$; OC_FARNELL: unknown; OC_NEWARK: 37M6104)  [TQFP44]
1  NC1:NC  nc
2  A:LRCKT  out
3  A:OCLK
4  A:GPSO_REQ  out
5  B:VSS_2  pwr
6  B:VDD_2  pwr
7  B:VSS_3  pwr
8  B:VDD_3  pwr
9  NC2:NC  nc
10  B:PVDD  pwr
11  B:PVSS  pwr
12  A:FILT  out
13  A:XTO  out
14  A:IODATA3
15  A:XTI  in
16  A:IODATA2
17  NC3:NC  nc
18  A:IODATA1
19  B:VSS_4  pwr
20  A:IODATA0
21  B:VDD_4  pwr
22  A:!TESTEN  in
23  NC4:NC  nc
24  A:SDI_ADC  in
25  A:!RESET  in
26  A:CRCK_ADC  in
27  A:DATA-REQ  out
28  A:GPSO_SCKL  out
29  B:VDD_1  pwr
30  B:VSS_1  pwr
31  A:SDA
32  A:SCL  in
33  A:GPSO_DATA  out
34  A:SDI  in
35  A:GPIO_STRB
36  A:SCKR  in
37  A:IODATA4
38  A:BIT_EN  in
39  A:IODATA5
40  A:SCK_ADC  in
41  A:IODATA6
42  A:SDO  out
43  A:IODATA7
44  A:SCKT  out

## Footprint TQFP44 (pad centres in mm)
Thin Quad Flat Pack package type TQ
smd 1.5 x 0.5: 1 -5.8,4; 2 -5.8,3.2; 3 -5.8,2.4; 4 -5.8,1.6; 5 -5.8,0.8; 6 -5.8,0; 7 -5.8,-0.8; 8 -5.8,-1.6; 9 -5.8,-2.4; 10 -5.8,-3.2; 11 -5.8,-4; 23 5.8,-4; 24 5.8,-3.2; 25 5.8,-2.4; 26 5.8,-1.6; 27 5.8,-0.8; 28 5.8,0; 29 5.8,0.8; 30 5.8,1.6; 31 5.8,2.4; 32 5.8,3.2; 33 5.8,4
smd 0.5 x 1.5: 12 -4,-5.8; 13 -3.2,-5.8; 14 -2.4,-5.8; 15 -1.6,-5.8; 16 -0.8,-5.8; 17 0,-5.8; 18 0.8,-5.8; 19 1.6,-5.8; 20 2.4,-5.8; 21 3.2,-5.8; 22 4,-5.8; 34 4,5.8; 35 3.2,5.8; 36 2.4,5.8; 37 1.6,5.8; 38 0.8,5.8; 39 0,5.8; 40 -0.8,5.8; 41 -1.6,5.8; 42 -2.4,5.8; 43 -3.2,5.8; 44 -4,5.8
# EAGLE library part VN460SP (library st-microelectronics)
SINGLE CHANNEL HIGH SIDE SMART POWER SOLID STATE RELAY http://eu.st.com/stonline/ 3732.pdf and 5691.pdf

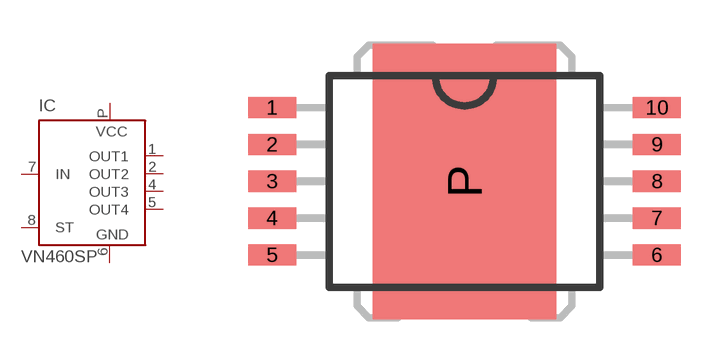
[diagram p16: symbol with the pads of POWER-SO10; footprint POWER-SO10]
Designator prefix IC

## VN460SP (MPN: VN460SP; OC_FARNELL: unknown; OC_NEWARK: 57P5296)  [POWER-SO10]
1  OUT1  out
2  OUT2  out
4  OUT3  out
5  OUT4  out
6  GND  pwr
7  IN  in
8  ST  in
P  VCC  pwr

## Footprint POWER-SO10 (pad centres in mm)
Power SO-10 http://eu.st.com/stonline/ 3732.pdf and 5691.pdf
smd 1.65 x 0.73: 1 -6.625,2.54; 2 -6.625,1.27; 3 -6.625,0; 4 -6.625,-1.27; 5 -6.625,-2.54; 6 6.625,-2.54; 7 6.625,-1.27; 8 6.625,0; 9 6.625,1.27; 10 6.625,2.54
smd 6.3 x 9.5: P 0,0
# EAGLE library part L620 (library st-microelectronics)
DMOS FULL BRIDGE DRIVER

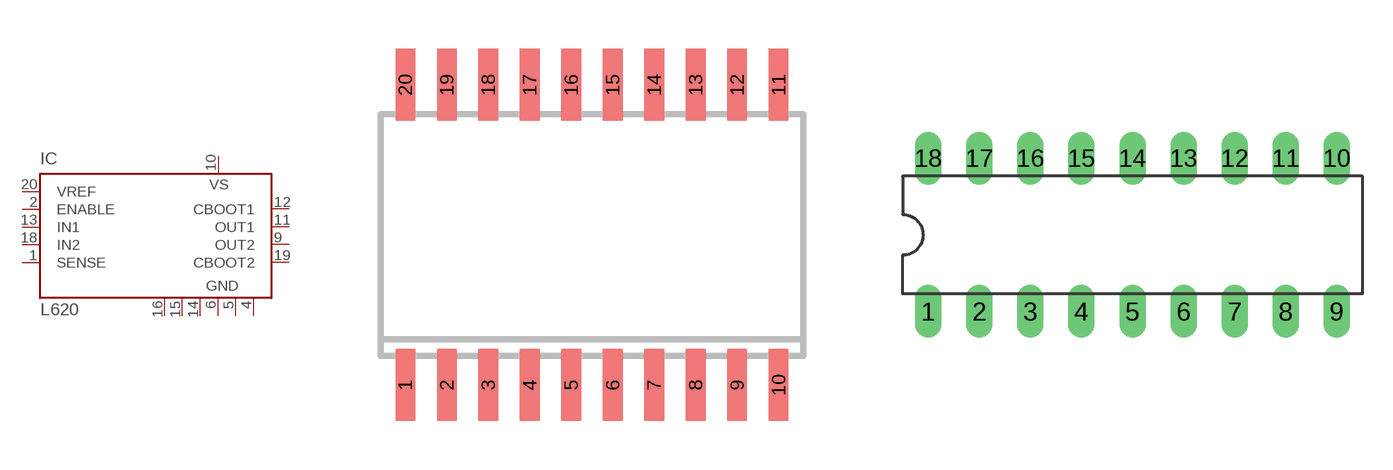
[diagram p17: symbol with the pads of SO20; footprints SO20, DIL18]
Designator prefix IC

## L6201 (MF: Arrow Electronics; MPN: L6201; OC_FARNELL: 1271290; OC_NEWARK: 89K0750)  [SO20]
1  SENSE  in
2  ENABLE  in
4  GND  pwr
5  GND  pwr
6  GND  pwr
9  OUT2  out
10  VS  pwr
11  OUT1  out
12  CBOOT1  in
13  IN1  in
14  GND  pwr
15  GND  pwr
16  GND  pwr
18  IN2  in
19  CBOOT2  in
20  VREF  in

## L6202 (MPN: L6202; OC_FARNELL: 1271291; OC_NEWARK: 26M0513)  [DIL18]
1  SENSE  in
2  ENABLE  in
4  GND  pwr
5  GND  pwr
6  GND  pwr
8  OUT2  out
9  VS  pwr
10  OUT1  out
11  CBOOT1  in
12  IN1  in
13  GND  pwr
14  GND  pwr
15  GND  pwr
16  IN2  in
17  CBOOT2  in
18  VREF  in

## Footprint SO20 (pad centres in mm)
SMALL OUTLINE INTEGRATED CIRCUIT wide body 7.5 mm/JEDEC MS-013AC
smd 0.6 x 2.2: 1 -5.715,-4.6; 2 -4.445,-4.6; 3 -3.175,-4.6; 4 -1.905,-4.6; 5 -0.635,-4.6; 6 0.635,-4.6; 7 1.905,-4.6; 8 3.175,-4.6; 9 4.445,-4.6; 10 5.715,-4.6; 11 5.715,4.6; 12 4.445,4.6; 13 3.175,4.6; 14 1.905,4.6; 15 0.635,4.6; 16 -0.635,4.6; 17 -1.905,4.6; 18 -3.175,4.6; 19 -4.445,4.6; 20 -5.715,4.6

## Footprint DIL18 (pad centres in mm)
Dual In Line Package
drill 0.813 long: 1 -10.16,-3.81; 2 -7.62,-3.81; 3 -5.08,-3.81; 4 -2.54,-3.81; 5 0,-3.81; 6 2.54,-3.81; 7 5.08,-3.81; 8 7.62,-3.81; 9 10.16,-3.81; 10 10.16,3.81; 11 7.62,3.81; 12 5.08,3.81; 13 2.54,3.81; 14 0,3.81; 15 -2.54,3.81; 16 -5.08,3.81; 17 -7.62,3.81; 18 -10.16,3.81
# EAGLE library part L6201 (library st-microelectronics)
DMOS FULL BRIDGE DRIVER

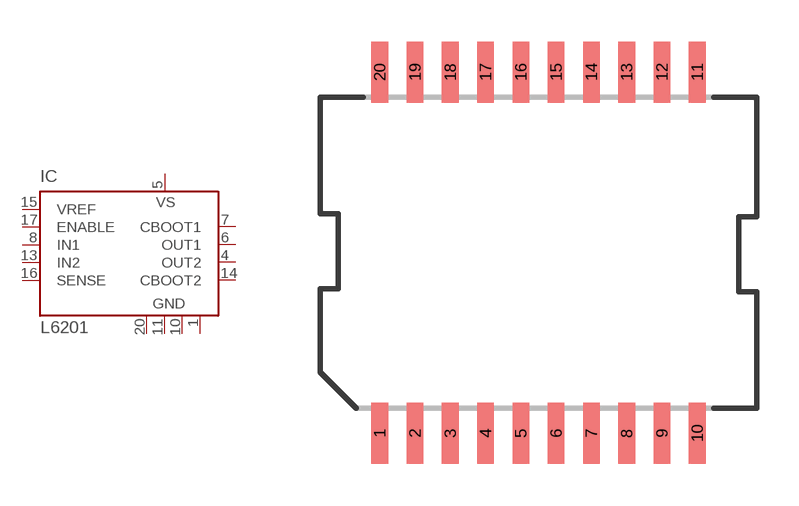
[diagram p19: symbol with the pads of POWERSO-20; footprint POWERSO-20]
Designator prefix IC

## L6201PS (MF: Arrow Electronics; MPN: L6201PS; OC_FARNELL: 1077146; OC_NEWARK: 89K0751)  [POWERSO-20]
1  GND  pwr
4  OUT2  out
5  VS  pwr
6  OUT1  out
7  CBOOT1  in
8  IN1  in
10  GND  pwr
11  GND  pwr
13  IN2  in
14  CBOOT2  in
15  VREF  in
16  SENSE  in
17  ENABLE  in
20  GND  pwr

## Footprint POWERSO-20 (pad centres in mm)
Power Small Outline
smd 0.6 x 2.2: 1 -5.715,-6.5; 2 -4.445,-6.5; 3 -3.175,-6.5; 4 -1.905,-6.5; 5 -0.635,-6.5; 6 0.635,-6.5; 7 1.905,-6.5; 8 3.175,-6.5; 9 4.445,-6.5; 10 5.715,-6.5; 11 5.715,6.5; 12 4.445,6.5; 13 3.175,6.5; 14 1.905,6.5; 15 0.635,6.5; 16 -0.635,6.5; 17 -1.905,6.5; 18 -3.175,6.5; 19 -4.445,6.5; 20 -5.715,6.5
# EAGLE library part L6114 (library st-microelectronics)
QUAD 100 V, DMOS SWITCH

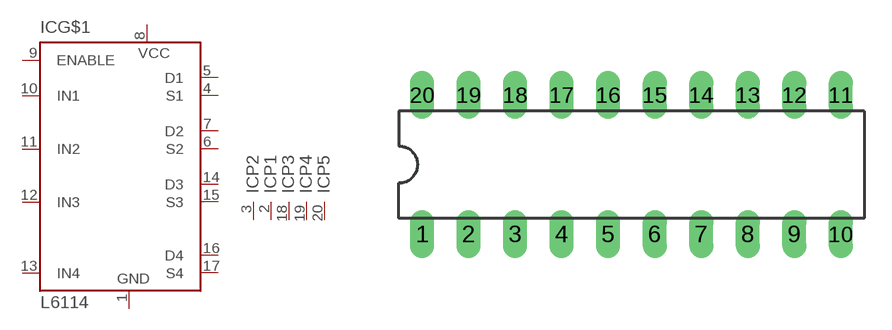
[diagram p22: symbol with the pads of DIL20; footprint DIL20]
Designator prefix IC; gates G$1=L6115 P2=GND P1=GND P3=GND P4=GND P5=GND

## L6114 (OC_FARNELL: unknown; OC_NEWARK: unknown)  [DIL20]
1  G$1:GND  pwr
2  P1:GND  pwr
3  P2:GND  pwr
4  G$1:S1  pas
5  G$1:D1  pas
6  G$1:S2  pas
7  G$1:D2  pas
8  G$1:VCC  pwr
9  G$1:ENABLE  in
10  G$1:IN1  in
11  G$1:IN2  in
12  G$1:IN3  in
13  G$1:IN4  in
14  G$1:D3  pas
15  G$1:S3  pas
16  G$1:D4  pas
17  G$1:S4  pas
18  P3:GND  pwr
19  P4:GND  pwr
20  P5:GND  pwr

## Footprint DIL20 (pad centres in mm)
Dual In Line Package
drill 0.813 long: 1 -11.43,-3.81; 2 -8.89,-3.81; 3 -6.35,-3.81; 4 -3.81,-3.81; 5 -1.27,-3.81; 6 1.27,-3.81; 7 3.81,-3.81; 8 6.35,-3.81; 9 8.89,-3.81; 10 11.43,-3.81; 11 11.43,3.81; 12 8.89,3.81; 13 6.35,3.81; 14 3.81,3.81; 15 1.27,3.81; 16 -1.27,3.81; 17 -3.81,3.81; 18 -6.35,3.81; 19 -8.89,3.81; 20 -11.43,3.81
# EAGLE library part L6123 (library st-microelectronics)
100 V DMOS SWITCHES

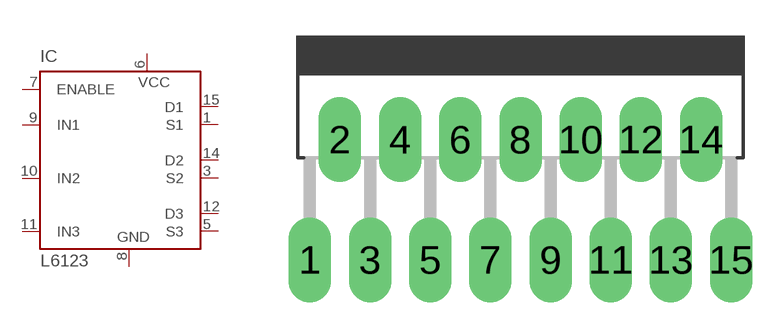
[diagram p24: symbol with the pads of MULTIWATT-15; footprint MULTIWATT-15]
Designator prefix IC

## L6123 (OC_FARNELL: unknown; OC_NEWARK: unknown)  [MULTIWATT-15]
1  S1  pas
3  S2  pas
5  S3  pas
6  VCC  pwr
7  ENABLE  in
8  GND  pwr
9  IN1  in
10  IN2  in
11  IN3  in
12  D3  pas
14  D2  pas
15  D1  pas

## Footprint MULTIWATT-15 (pad centres in mm)
Multiwatt 15 lead
drill 1.2 long: 1 -8.89,-7.62; 2 -7.62,-2.54; 3 -6.35,-7.62; 4 -5.08,-2.54; 5 -3.81,-7.62; 6 -2.54,-2.54; 7 -1.27,-7.62; 8 0,-2.54; 9 1.27,-7.62; 10 2.54,-2.54; 11 3.81,-7.62; 12 5.08,-2.54; 13 6.35,-7.62; 14 7.62,-2.54; 15 8.89,-7.62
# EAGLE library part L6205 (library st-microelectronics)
DUAL DMOS FULL BRIDGE MOTOR DRIVER

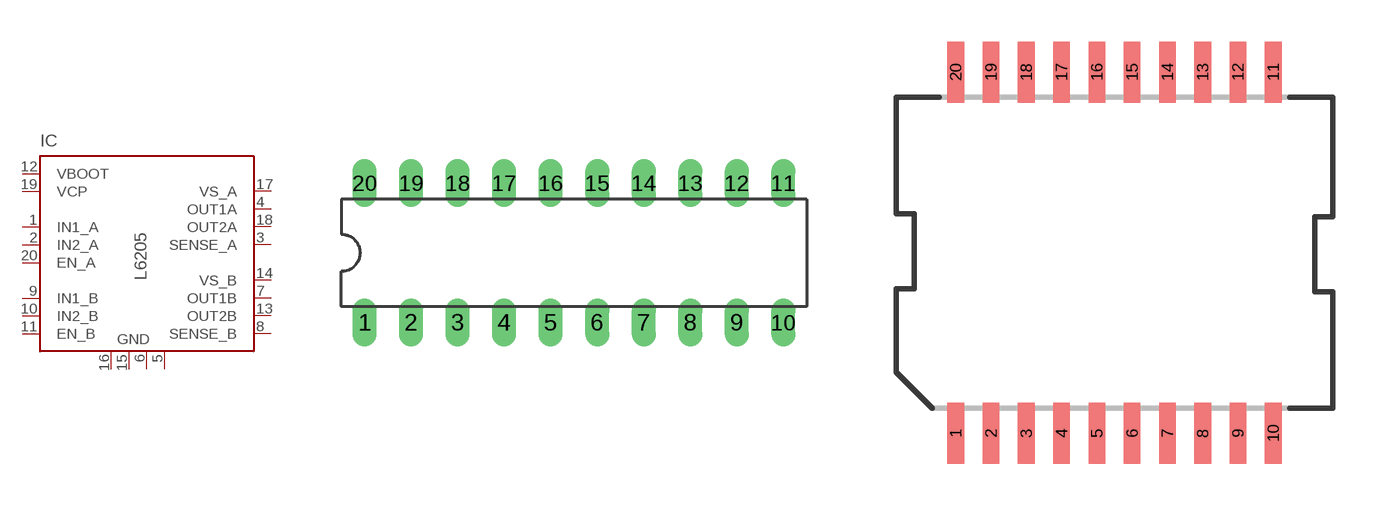
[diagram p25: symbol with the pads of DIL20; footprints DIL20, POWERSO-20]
Designator prefix IC

## L6205N (MF: Arrow Electronics; MPN: L6205N; OC_FARNELL: 1564367; OC_NEWARK: 89K0754)  [DIL20]
1  IN1_A  in
2  IN2_A  in
3  SENSE_A  in
4  OUT1A  out
5  GND  pwr
6  GND  pwr
7  OUT1B  out
8  SENSE_B  in
9  IN1_B  in
10  IN2_B  in
11  EN_B  in
12  VBOOT  pwr
13  OUT2B  out
14  VS_B  pwr
15  GND  pwr
16  GND  pwr
17  VS_A  pwr
18  OUT2A  out
19  VCP  pwr
20  EN_A  in

## L6205PD (MF: Arrow Electronics; MPN: L6205PD; OC_FARNELL: unknown; OC_NEWARK: 89K0755)  [POWERSO-20]
1  GND  pwr
2  VS_A  pwr
3  OUT2A  out
4  VCP  pwr
5  EN_A  in
6  IN1_A  in
7  IN2_A  in
8  SENSE_A  in
9  OUT1A  out
10  GND  pwr
11  GND  pwr
12  OUT1B  out
13  SENSE_B  in
14  IN1_B  in
15  IN2_B  in
16  EN_B  in
17  VBOOT  pwr
18  OUT2B  out
19  VS_B  pwr
20  GND  pwr

## L6205D (MPN: L6205D; OC_FARNELL: unknown; OC_NEWARK: 37M3487)  [SO20]
Pads as for DIL20

## Footprint DIL20 (pad centres in mm)
Dual In Line Package
drill 0.813 long: 1 -11.43,-3.81; 2 -8.89,-3.81; 3 -6.35,-3.81; 4 -3.81,-3.81; 5 -1.27,-3.81; 6 1.27,-3.81; 7 3.81,-3.81; 8 6.35,-3.81; 9 8.89,-3.81; 10 11.43,-3.81; 11 11.43,3.81; 12 8.89,3.81; 13 6.35,3.81; 14 3.81,3.81; 15 1.27,3.81; 16 -1.27,3.81; 17 -3.81,3.81; 18 -6.35,3.81; 19 -8.89,3.81; 20 -11.43,3.81

## Footprint POWERSO-20 (pad centres in mm)
Power Small Outline
smd 0.6 x 2.2: 1 -5.715,-6.5; 2 -4.445,-6.5; 3 -3.175,-6.5; 4 -1.905,-6.5; 5 -0.635,-6.5; 6 0.635,-6.5; 7 1.905,-6.5; 8 3.175,-6.5; 9 4.445,-6.5; 10 5.715,-6.5; 11 5.715,6.5; 12 4.445,6.5; 13 3.175,6.5; 14 1.905,6.5; 15 0.635,6.5; 16 -0.635,6.5; 17 -1.905,6.5; 18 -3.175,6.5; 19 -4.445,6.5; 20 -5.715,6.5

## Footprint SO20 (pad centres in mm)
SMALL OUTLINE INTEGRATED CIRCUIT wide body 7.5 mm/JEDEC MS-013AC
smd 0.6 x 2.2: 1 -5.715,-4.6; 2 -4.445,-4.6; 3 -3.175,-4.6; 4 -1.905,-4.6; 5 -0.635,-4.6; 6 0.635,-4.6; 7 1.905,-4.6; 8 3.175,-4.6; 9 4.445,-4.6; 10 5.715,-4.6; 11 5.715,4.6; 12 4.445,4.6; 13 3.175,4.6; 14 1.905,4.6; 15 0.635,4.6; 16 -0.635,4.6; 17 -1.905,4.6; 18 -3.175,4.6; 19 -4.445,4.6; 20 -5.715,4.6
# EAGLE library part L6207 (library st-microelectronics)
DUAL DMOS FULL BRIDGE MOTOR DRIVER

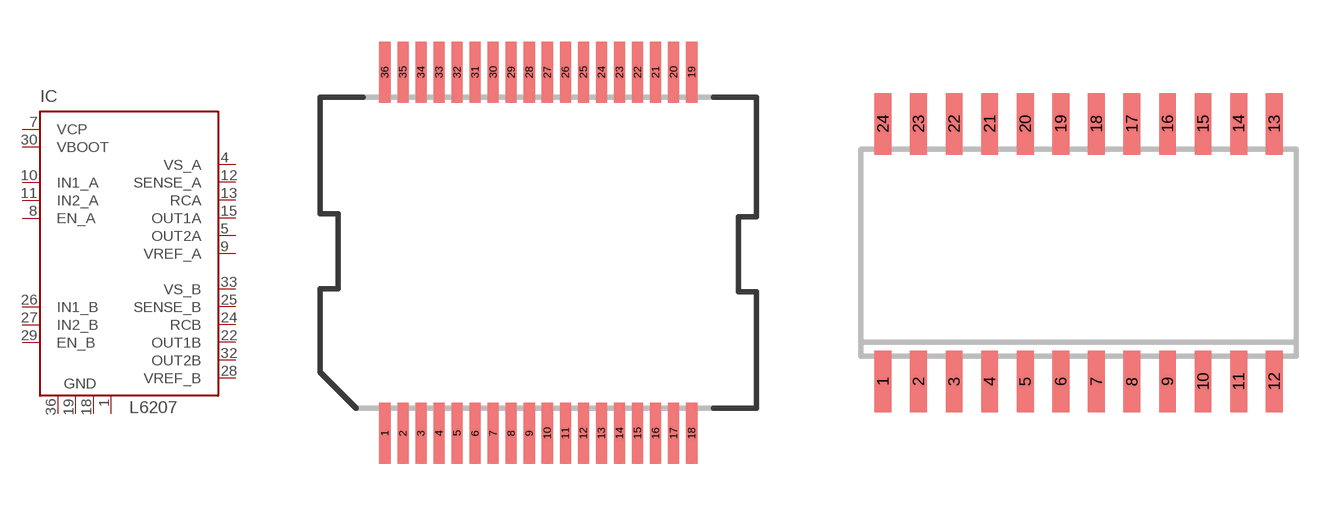
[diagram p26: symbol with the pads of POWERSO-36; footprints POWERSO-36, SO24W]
Designator prefix IC

## L6207PSO36 (OC_FARNELL: unknown; OC_NEWARK: 56P8448)  [POWERSO-36]
1  GND  pwr
4  VS_A  pwr
5  OUT2A  out
7  VCP  pwr
8  EN_A  in
9  VREF_A  in
10  IN1_A  in
11  IN2_A  in
12  SENSE_A  in
13  RCA  in
15  OUT1A  out
18  GND  pwr
19  GND  pwr
22  OUT1B  out
24  RCB  in
25  SENSE_B  in
26  IN1_B  in
27  IN2_B  in
28  VREF_B  in
29  EN_B  in
30  VBOOT  pwr
32  OUT2B  out
33  VS_B  pwr
36  GND  pwr

## L6207D (MPN: L6207D; OC_FARNELL: unknown; OC_NEWARK: 42M9976)  [SO24W]
1  IN1_A  in
2  IN2_A  in
3  SENSE_A  in
4  RCA  in
5  OUT1A  out
6  GND  pwr
7  GND  pwr
8  OUT1B  out
9  RCB  in
10  SENSE_B  in
11  IN2_B  in
12  IN1_B  in
13  VREF_B  in
14  EN_B  in
15  VBOOT  pwr
16  OUT2B  out
17  VS_B  pwr
18  GND  pwr
19  GND  pwr
20  VS_A  pwr
21  OUT2A  out
22  VCP  pwr
23  EN_A  in
24  VREF_A  in

## L6207N (MPN: L6207N; OC_FARNELL: unknown; OC_NEWARK: 56P8447)  [DIL24S]
Pads as for SO24W

## Footprint POWERSO-36 (pad centres in mm)
Power Small Outline
smd 0.4 x 2.2: 1 -5.525,-6.5; 2 -4.875,-6.5; 3 -4.225,-6.5; 4 -3.575,-6.5; 5 -2.925,-6.5; 6 -2.275,-6.5; 7 -1.625,-6.5; 8 -0.975,-6.5; 9 -0.325,-6.5; 10 0.325,-6.5; 11 0.975,-6.5; 12 1.625,-6.5; 13 2.275,-6.5; 14 2.925,-6.5; 15 3.575,-6.5; 16 4.225,-6.5; 17 4.875,-6.5; 18 5.525,-6.5; 19 5.525,6.5; 20 4.875,6.5; 21 4.225,6.5; 22 3.575,6.5; 23 2.925,6.5; 24 2.275,6.5; 25 1.625,6.5; 26 0.975,6.5; 27 0.325,6.5; 28 -0.325,6.5; 29 -0.975,6.5; 30 -1.625,6.5; 31 -2.275,6.5; 32 -2.925,6.5; 33 -3.575,6.5; 34 -4.225,6.5; 35 -4.875,6.5; 36 -5.525,6.5

## Footprint SO24W (pad centres in mm)
SMALL OUTLINE INTEGRATED CIRCUIT wide body 7.5 mm/JEDEC MO-119AA
smd 0.6 x 2.2: 1 -6.985,-4.6; 2 -5.715,-4.6; 3 -4.445,-4.6; 4 -3.175,-4.6; 5 -1.905,-4.6; 6 -0.635,-4.6; 7 0.635,-4.6; 8 1.905,-4.6; 9 3.175,-4.6; 10 4.445,-4.6; 11 5.715,-4.6; 12 6.985,-4.6; 13 6.985,4.6; 14 5.715,4.6; 15 4.445,4.6; 16 3.175,4.6; 17 1.905,4.6; 18 0.635,4.6; 19 -0.635,4.6; 20 -1.905,4.6; 21 -3.175,4.6; 22 -4.445,4.6; 23 -5.715,4.6; 24 -6.985,4.6

## Footprint DIL24S (pad centres in mm)
Dual In Line Package Small
drill 0.813 long: 1 -13.97,-3.81; 2 -11.43,-3.81; 3 -8.89,-3.81; 4 -6.35,-3.81; 5 -3.81,-3.81; 6 -1.27,-3.81; 7 1.27,-3.81; 8 3.81,-3.81; 9 6.35,-3.81; 10 8.89,-3.81; 11 11.43,-3.81; 12 13.97,-3.81; 13 13.97,3.81; 14 11.43,3.81; 15 8.89,3.81; 16 6.35,3.81; 17 3.81,3.81; 18 1.27,3.81; 19 -1.27,3.81; 20 -3.81,3.81; 21 -6.35,3.81; 22 -8.89,3.81; 23 -11.43,3.81; 24 -13.97,3.81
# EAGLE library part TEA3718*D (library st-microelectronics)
STEPPER MOTOR DRIVER

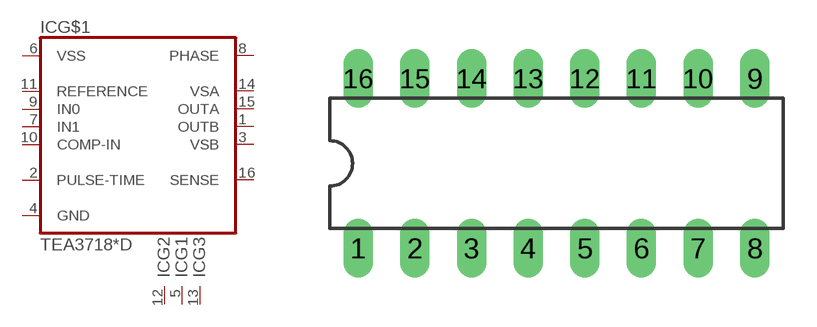
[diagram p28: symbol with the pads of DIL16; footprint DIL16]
Designator prefix IC; gates G$1=TAE3718D G2=GND G1=GND G3=GND

## TEA3718DP (MPN: E-TEA3718DP; OC_FARNELL: 1159696; OC_NEWARK: 91K9593), TEA3718SDP (MPN: E-TEA3718SDP; OC_FARNELL: unknown; OC_NEWARK: 56P7421)  [DIL16]
1  G$1:OUTB  out
2  G$1:PULSE-TIME  pas
3  G$1:VSB  pwr
4  G$1:GND  pwr
5  G1:GND  pwr
6  G$1:VSS  pwr
7  G$1:IN1  in
8  G$1:PHASE  in
9  G$1:IN0  in
10  G$1:COMP-IN  in
11  G$1:REFERENCE  in
12  G2:GND  pwr
13  G3:GND  pwr
14  G$1:VSA  pwr
15  G$1:OUTA  out
16  G$1:SENSE  in

## Footprint DIL16 (pad centres in mm)
Dual In Line Package
drill 0.813 long: 1 -8.89,-3.81; 2 -6.35,-3.81; 3 -3.81,-3.81; 4 -1.27,-3.81; 5 1.27,-3.81; 6 3.81,-3.81; 7 6.35,-3.81; 8 8.89,-3.81; 9 8.89,3.81; 10 6.35,3.81; 11 3.81,3.81; 12 1.27,3.81; 13 -1.27,3.81; 14 -3.81,3.81; 15 -6.35,3.81; 16 -8.89,3.81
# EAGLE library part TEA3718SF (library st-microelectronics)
STEPPER MOTOR DRIVER

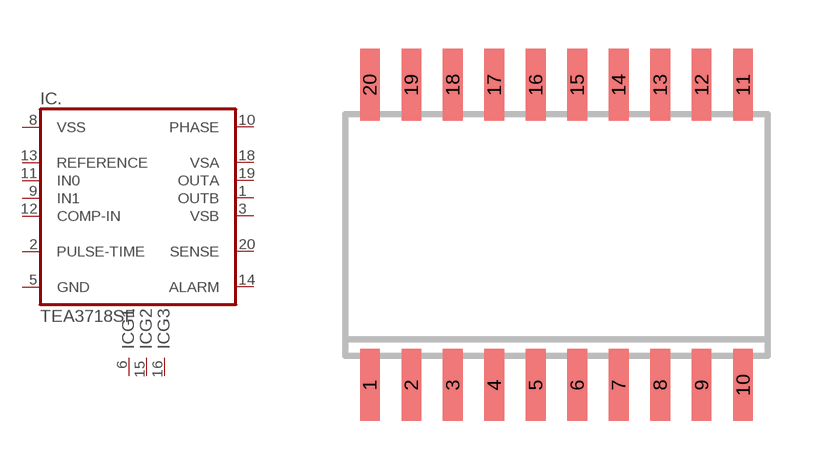
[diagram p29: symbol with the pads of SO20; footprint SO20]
Designator prefix IC; gates .=TAE3718 G1=GND G2=GND G3=GND

## TEA3718SFP (MPN: E-TEA3718SFP; OC_FARNELL: unknown; OC_NEWARK: 56P7422)  [SO20]
1  .:OUTB  out
2  .:PULSE-TIME  pas
3  .:VSB  pwr
5  .:GND  pwr
6  G1:GND  pwr
8  .:VSS  pwr
9  .:IN1  in
10  .:PHASE  in
11  .:IN0  in
12  .:COMP-IN  in
13  .:REFERENCE  in
14  .:ALARM  oc
15  G2:GND  pwr
16  G3:GND  pwr
18  .:VSA  pwr
19  .:OUTA  out
20  .:SENSE  in

## Footprint SO20 (pad centres in mm)
SMALL OUTLINE INTEGRATED CIRCUIT wide body 7.5 mm/JEDEC MS-013AC
smd 0.6 x 2.2: 1 -5.715,-4.6; 2 -4.445,-4.6; 3 -3.175,-4.6; 4 -1.905,-4.6; 5 -0.635,-4.6; 6 0.635,-4.6; 7 1.905,-4.6; 8 3.175,-4.6; 9 4.445,-4.6; 10 5.715,-4.6; 11 5.715,4.6; 12 4.445,4.6; 13 3.175,4.6; 14 1.905,4.6; 15 0.635,4.6; 16 -0.635,4.6; 17 -1.905,4.6; 18 -3.175,4.6; 19 -4.445,4.6; 20 -5.715,4.6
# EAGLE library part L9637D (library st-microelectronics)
ISO 9141 INTERFACE Source: 1765.pdf

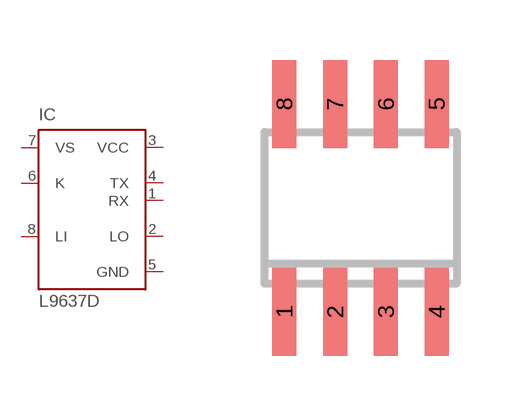
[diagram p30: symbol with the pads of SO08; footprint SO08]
Designator prefix IC

## L9637D (MPN: L9637D; OC_FARNELL: unknown; OC_NEWARK: 56P8926)  [SO08]
1  RX  out
2  LO  out
3  VCC  pwr
4  TX  in
5  GND  pwr
6  K  in
7  VS  pwr
8  LI  in

## Footprint SO08 (pad centres in mm)
SMALL OUTLINE INTEGRATED CIRCUIT body 3.9 mm/JEDEC MS-012AA
smd 0.6 x 2.2: 1 -1.905,-2.6; 2 -0.635,-2.6; 3 0.635,-2.6; 4 1.905,-2.6; 5 1.905,2.6; 6 0.635,2.6; 7 -0.635,2.6; 8 -1.905,2.6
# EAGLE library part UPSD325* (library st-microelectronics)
8032 Microcontroller Core with Flash Programmable System Devices and 256 Kbit SRAM Sourece: www.st.com/stonline/books/pdf/docs/9202.pdf

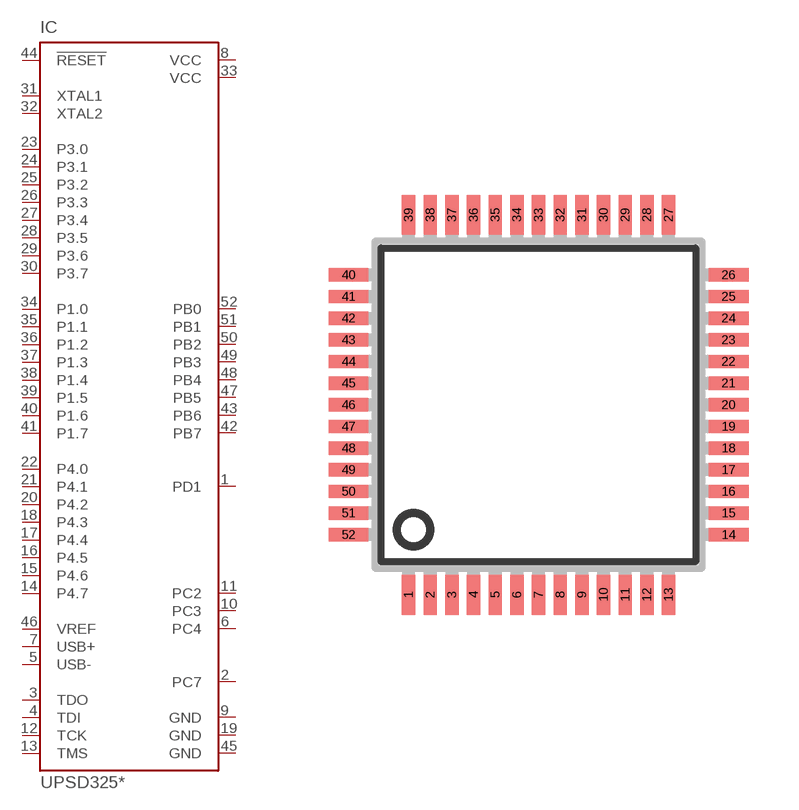
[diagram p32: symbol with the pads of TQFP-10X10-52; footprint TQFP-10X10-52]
Designator prefix IC

## UPSD3253B-40T6 (MPN: UPSD3253B-40T6; OC_FARNELL: unknown; OC_NEWARK: 57P4778), UPSD3253BV-24T6 (MPN: UPSD3253BV-24T6; OC_FARNELL: unknown; OC_NEWARK: 37M9123), UPSD3254A-40T6 (MPN: UPSD3254A-40T6; OC_FARNELL: unknown; OC_NEWARK: 57P4780)  [TQFP-10X10-52]
1  PD1
2  PC7
3  TDO  out
4  TDI  in
5  USB-
6  PC4
7  USB+
8  VCC  pwr
9  GND  pwr
10  PC3
11  PC2
12  TCK  in
13  TMS  in
14  P4.7
15  P4.6
16  P4.5
17  P4.4
18  P4.3
19  GND  pwr
20  P4.2
21  P4.1
22  P4.0
23  P3.0
24  P3.1
25  P3.2
26  P3.3
27  P3.4
28  P3.5
29  P3.6
30  P3.7
31  XTAL1  in
32  XTAL2  out
33  VCC  pwr
34  P1.0
35  P1.1
36  P1.2
37  P1.3
38  P1.4
39  P1.5
40  P1.6
41  P1.7
42  PB7
43  PB6
44  !RESET  in
45  GND  pwr
46  VREF  out
47  PB5
48  PB4
49  PB3
50  PB2
51  PB1
52  PB0

## Footprint TQFP-10X10-52 (pad centres in mm)
TQFP52 Source: www.st.com/stonline/books/pdf/docs/9202.pdf
smd 0.4 x 1.2: 1 -3.9,-5.7; 2 -3.25,-5.7; 3 -2.6,-5.7; 4 -1.95,-5.7; 5 -1.3,-5.7; 6 -0.65,-5.7; 7 0,-5.7; 8 0.65,-5.7; 9 1.3,-5.7; 10 1.95,-5.7; 11 2.6,-5.7; 12 3.25,-5.7; 13 3.9,-5.7; 27 3.9,5.7; 28 3.25,5.7; 29 2.6,5.7; 30 1.95,5.7; 31 1.3,5.7; 32 0.65,5.7; 33 0,5.7; 34 -0.65,5.7; 35 -1.3,5.7; 36 -1.95,5.7; 37 -2.6,5.7; 38 -3.25,5.7; 39 -3.9,5.7
smd 1.2 x 0.4: 14 5.7,-3.9; 15 5.7,-3.25; 16 5.7,-2.6; 17 5.7,-1.95; 18 5.7,-1.3; 19 5.7,-0.65; 20 5.7,0; 21 5.7,0.65; 22 5.7,1.3; 23 5.7,1.95; 24 5.7,2.6; 25 5.7,3.25; 26 5.7,3.9; 40 -5.7,3.9; 41 -5.7,3.25; 42 -5.7,2.6; 43 -5.7,1.95; 44 -5.7,1.3; 45 -5.7,0.65; 46 -5.7,0; 47 -5.7,-0.65; 48 -5.7,-1.3; 49 -5.7,-1.95; 50 -5.7,-2.6; 51 -5.7,-3.25; 52 -5.7,-3.9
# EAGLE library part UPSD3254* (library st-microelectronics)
8032 Microcontroller Core with Flash Programmable System Devices and 256 Kbit SRAM Sourece: www.st.com/stonline/books/pdf/docs/9202.pdf

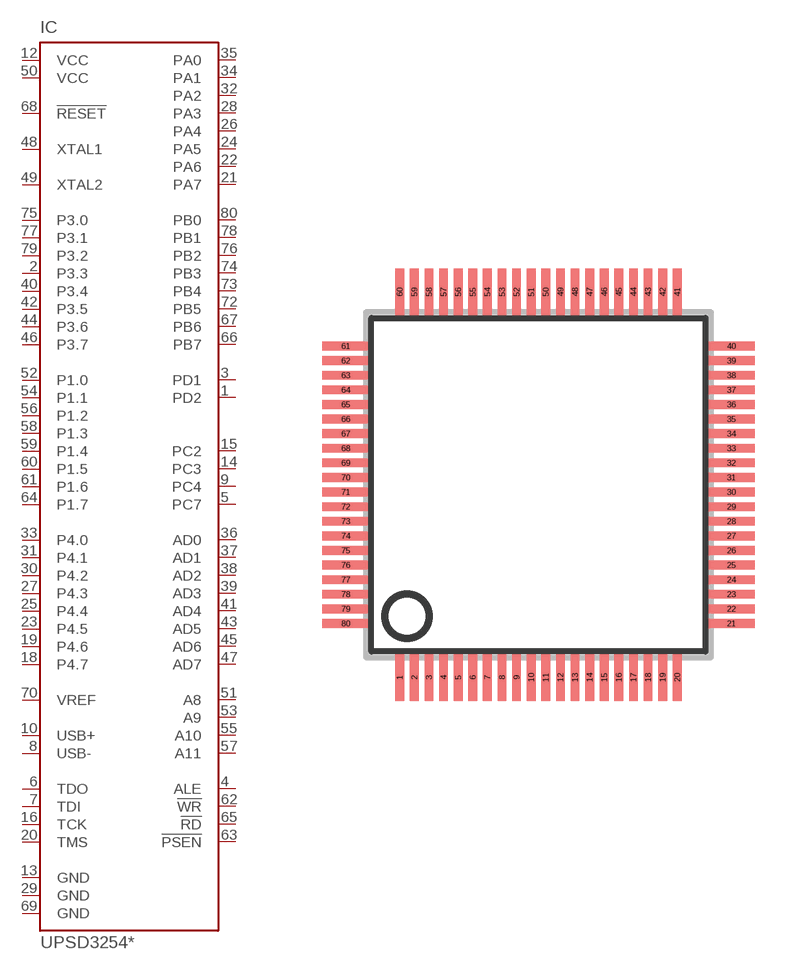
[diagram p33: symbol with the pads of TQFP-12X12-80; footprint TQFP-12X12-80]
Designator prefix IC

## UPSD3254A-40U6 (MPN: UPSD3254A-40U6; OC_FARNELL: 1796098; OC_NEWARK: 37M9124), UPSD3254BV-24U6 (MPN: UPSD3254BV-24U6; OC_FARNELL: unknown; OC_NEWARK: 57P4782)  [TQFP-12X12-80]
1  PD2
2  P3.3
3  PD1
4  ALE  out
5  PC7
6  TDO  out
7  TDI  in
8  USB-
9  PC4
10  USB+
12  VCC  pwr
13  GND  pwr
14  PC3
15  PC2
16  TCK  in
18  P4.7
19  P4.6
20  TMS  in
21  PA7
22  PA6
23  P4.5
24  PA5
25  P4.4
26  PA4
27  P4.3
28  PA3
29  GND  pwr
30  P4.2
31  P4.1
32  PA2
33  P4.0
34  PA1
35  PA0
36  AD0  in
37  AD1  in
38  AD2  in
39  AD3  in
40  P3.4
41  AD4  in
42  P3.5
43  AD5  in
44  P3.6
45  AD6  in
46  P3.7
47  AD7  in
48  XTAL1  in
49  XTAL2  out
50  VCC  pwr
51  A8  out
52  P1.0
53  A9  out
54  P1.1
55  A10  out
56  P1.2
57  A11  out
58  P1.3
59  P1.4
60  P1.5
61  P1.6
62  !WR  out
63  !PSEN  out
64  P1.7
65  !RD  out
66  PB7
67  PB6
68  !RESET  in
69  GND  pwr
70  VREF  out
72  PB5
73  PB4
74  PB3
75  P3.0
76  PB2
77  P3.1
78  PB1
79  P3.2
80  PB0

## Footprint TQFP-12X12-80 (pad centres in mm)
TQFP80 Source: www.st.com/stonline/books/pdf/docs/9202.pdf
smd 0.3 x 1.6: 1 -4.75,-6.6; 2 -4.25,-6.6; 3 -3.75,-6.6; 4 -3.25,-6.6; 5 -2.75,-6.6; 6 -2.25,-6.6; 7 -1.75,-6.6; 8 -1.25,-6.6; 9 -0.75,-6.6; 10 -0.25,-6.6; 11 0.25,-6.6; 12 0.75,-6.6; 13 1.25,-6.6; 14 1.75,-6.6; 15 2.25,-6.6; 16 2.75,-6.6; 17 3.25,-6.6; 18 3.75,-6.6; 19 4.25,-6.6; 20 4.75,-6.6; 41 4.75,6.6; 42 4.25,6.6; 43 3.75,6.6; 44 3.25,6.6; 45 2.75,6.6; 46 2.25,6.6; 47 1.75,6.6; 48 1.25,6.6; 49 0.75,6.6; 50 0.25,6.6; 51 -0.25,6.6; 52 -0.75,6.6; 53 -1.25,6.6; 54 -1.75,6.6; 55 -2.25,6.6; 56 -2.75,6.6; 57 -3.25,6.6; 58 -3.75,6.6; 59 -4.25,6.6; 60 -4.75,6.6
smd 1.6 x 0.3: 21 6.6,-4.75; 22 6.6,-4.25; 23 6.6,-3.75; 24 6.6,-3.25; 25 6.6,-2.75; 26 6.6,-2.25; 27 6.6,-1.75; 28 6.6,-1.25; 29 6.6,-0.75; 30 6.6,-0.25; 31 6.6,0.25; 32 6.6,0.75; 33 6.6,1.25; 34 6.6,1.75; 35 6.6,2.25; 36 6.6,2.75; 37 6.6,3.25; 38 6.6,3.75; 39 6.6,4.25; 40 6.6,4.75; 61 -6.6,4.75; 62 -6.6,4.25; 63 -6.6,3.75; 64 -6.6,3.25; 65 -6.6,2.75; 66 -6.6,2.25; 67 -6.6,1.75; 68 -6.6,1.25; 69 -6.6,0.75; 70 -6.6,0.25; 71 -6.6,-0.25; 72 -6.6,-0.75; 73 -6.6,-1.25; 74 -6.6,-1.75; 75 -6.6,-2.25; 76 -6.6,-2.75; 77 -6.6,-3.25; 78 -6.6,-3.75; 79 -6.6,-4.25; 80 -6.6,-4.75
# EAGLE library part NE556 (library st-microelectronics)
General Purpose Biopolartimer

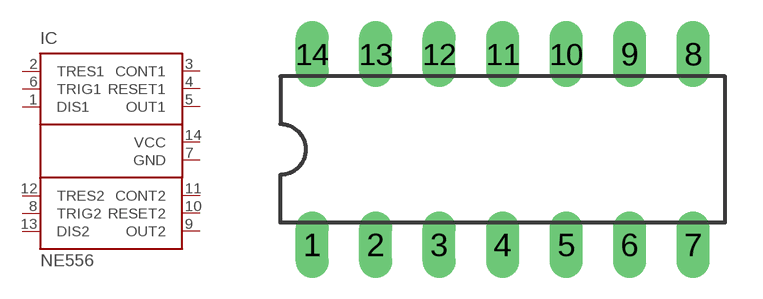
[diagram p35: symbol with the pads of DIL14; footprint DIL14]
Designator prefix IC

## NE556 (MPN: NE556; OC_FARNELL: 2349784; OC_NEWARK: 83C0108)  [DIL14]
1  DIS1  in
2  TRES1  in
3  CONT1  in
4  RESET1  in
5  OUT1  out
6  TRIG1  in
7  GND  pwr
8  TRIG2  in
9  OUT2  out
10  RESET2  in
11  CONT2  in
12  TRES2  in
13  DIS2  in
14  VCC  pwr

## Footprint DIL14 (pad centres in mm)
Dual In Line Package
drill 0.813 long: 1 -7.62,-3.81; 2 -5.08,-3.81; 3 -2.54,-3.81; 4 0,-3.81; 5 2.54,-3.81; 6 5.08,-3.81; 7 7.62,-3.81; 8 7.62,3.81; 9 5.08,3.81; 10 2.54,3.81; 11 0,3.81; 12 -2.54,3.81; 13 -5.08,3.81; 14 -7.62,3.81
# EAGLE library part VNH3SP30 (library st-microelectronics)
FULLY INTEGRATED H-BRIDGE MOTOR DRIVER Source: http://pdf1.alldatasheet.com/datasheet-pdf/view/84563/STMICROELECTRONICS/VNH3SP30.html

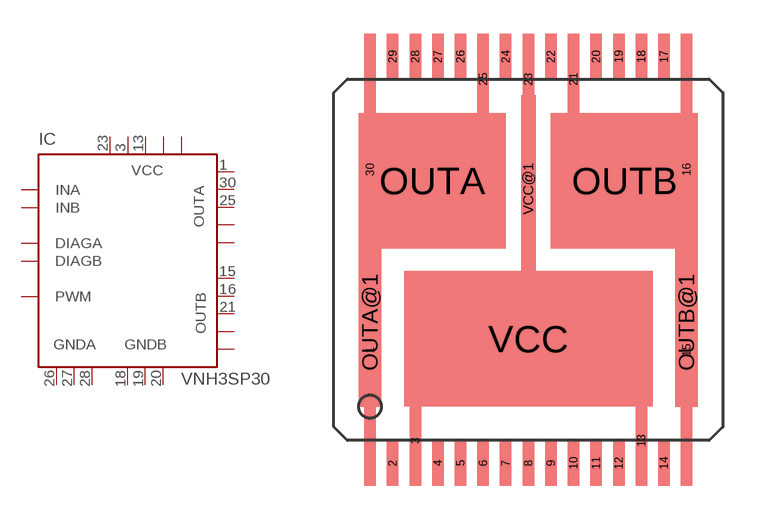
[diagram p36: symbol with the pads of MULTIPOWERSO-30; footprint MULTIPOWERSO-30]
Designator prefix IC

## VNH3SP30 (MPN: VNH3SP30-E; OC_FARNELL: 1739420; OC_NEWARK: 33R1486)  [MULTIPOWERSO-30]
1  OUTA  out
3  VCC  pwr
5  INA  in
6  DIAGA  oc
8  PWM  in
10  DIAGB  oc
11  INB  in
13  VCC  pwr
15  OUTB  out
16  OUTB  pas
18  GNDB  pwr
19  GNDB  pwr
20  GNDB  pwr
21  OUTB  pas
23  VCC  pwr
25  OUTA  pas
26  GNDA  pwr
27  GNDA  pwr
28  GNDA  pwr
30  OUTA  pas
OUTA  OUTA  pas
OUTA@1  OUTA  pas
OUTB  OUTB  pas
OUTB@1  OUTB  pas
VCC  VCC  pwr
VCC@1  VCC  pwr

## Footprint MULTIPOWERSO-30 (pad centres in mm)
MultiPowerSO-30 Source: http://pdf1.alldatasheet.com/datasheet-pdf/view/84563/STMICROELECTRONICS/VNH3SP30.html
smd 0.508 x 12: 1 -7,-4; 15 7,-4; 16 7,4; 30 -7,4
smd 0.508 x 2: 2 -6,-9; 4 -4,-9; 5 -3,-9; 6 -2,-9; 7 -1,-9; 8 0,-9; 9 1,-9; 10 2,-9; 11 3,-9; 12 4,-9; 14 6,-9; 17 6,9; 18 5,9; 19 4,9; 20 3,9; 22 1,9; 24 -1,9; 26 -3,9; 27 -4,9; 28 -5,9; 29 -6,9
smd 0.508 x 4: 3 -5,-8; 13 5,-8; 21 2,8; 23 0,8; 25 -2,8
smd 6.5 x 6: OUTA -4.25,3.5; OUTB 4.25,3.5
smd 1 x 7.5: OUTA@1 -7,-2.755; OUTB@1 7,-2.755
smd 11 x 6: VCC 0,-3.5
smd 0.65 x 8.3: VCC@1 0,3.145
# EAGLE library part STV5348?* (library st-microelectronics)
Monochip Teletext And VPS Decoder with 8 integrated pages

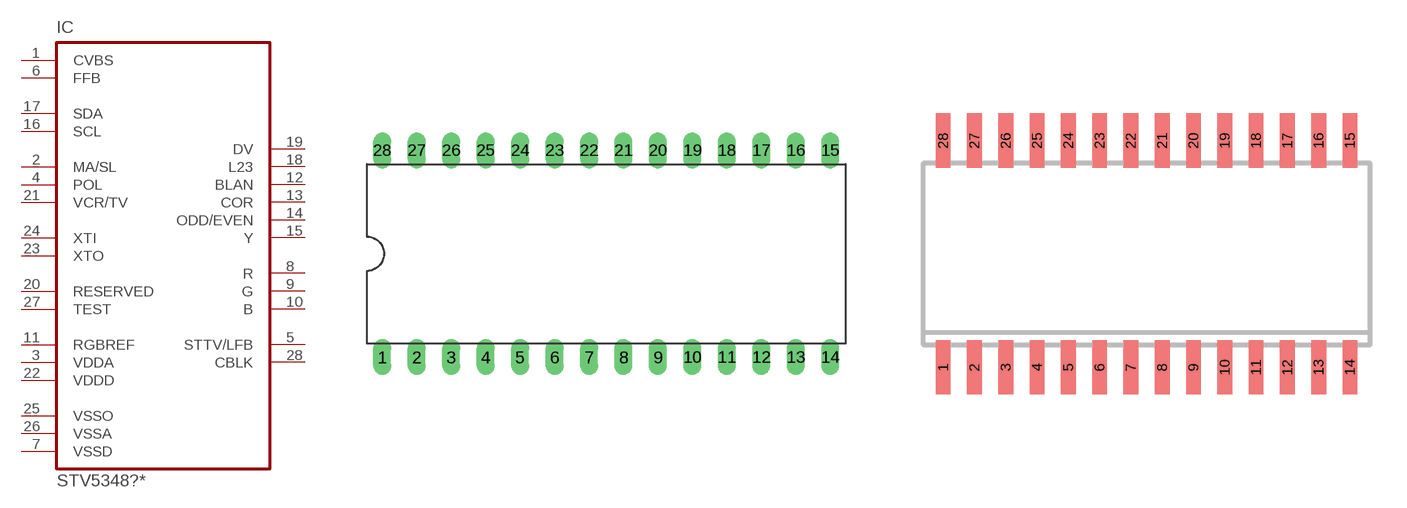
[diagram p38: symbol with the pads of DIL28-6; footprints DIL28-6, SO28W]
Designator prefix IC

## STV5348 (OC_FARNELL: unknown; OC_NEWARK: unknown), STV5348/H (OC_FARNELL: unknown; OC_NEWARK: unknown), STV5348/T (OC_FARNELL: unknown; OC_NEWARK: unknown)  [DIL28-6]
1  CVBS  in
2  MA/SL  in
3  VDDA  pwr
4  POL  in
5  STTV/LFB
6  FFB  in
7  VSSD  pwr
8  R  out
9  G  out
10  B  out
11  RGBREF  pwr
12  BLAN  out
13  COR  oc
14  ODD/EVEN  out
15  Y  oc
16  SCL  in
17  SDA
18  L23  out
19  DV  out
20  RESERVED  pas
21  VCR/TV  in
22  VDDD  pwr
23  XTO  out
24  XTI  in
25  VSSO  pwr
26  VSSA  pwr
27  TEST  pas
28  CBLK

## STV5348D (OC_FARNELL: unknown; OC_NEWARK: unknown), STV5348D/T (OC_FARNELL: unknown; OC_NEWARK: unknown)  [SO28W]
Pads as for DIL28-6

## Footprint DIL28-6 (pad centres in mm)
Dual In Line Package 0.6 inch
drill 0.813 long: 1 -16.51,-7.62; 2 -13.97,-7.62; 3 -11.43,-7.62; 4 -8.89,-7.62; 5 -6.35,-7.62; 6 -3.81,-7.62; 7 -1.27,-7.62; 8 1.27,-7.62; 9 3.81,-7.62; 10 6.35,-7.62; 11 8.89,-7.62; 12 11.43,-7.62; 13 13.97,-7.62; 14 16.51,-7.62; 15 16.51,7.62; 16 13.97,7.62; 17 11.43,7.62; 18 8.89,7.62; 19 6.35,7.62; 20 3.81,7.62; 21 1.27,7.62; 22 -1.27,7.62; 23 -3.81,7.62; 24 -6.35,7.62; 25 -8.89,7.62; 26 -11.43,7.62; 27 -13.97,7.62; 28 -16.51,7.62

## Footprint SO28W (pad centres in mm)
SMALL OUTLINE INTEGRATED CIRCUIT wide body 7.5 mm/JEDEC MO-119AB
smd 0.6 x 2.2: 1 -8.255,-4.6; 2 -6.985,-4.6; 3 -5.715,-4.6; 4 -4.445,-4.6; 5 -3.175,-4.6; 6 -1.905,-4.6; 7 -0.635,-4.6; 8 0.635,-4.6; 9 1.905,-4.6; 10 3.175,-4.6; 11 4.445,-4.6; 12 5.715,-4.6; 13 6.985,-4.6; 14 8.255,-4.6; 15 8.255,4.6; 16 6.985,4.6; 17 5.715,4.6; 18 4.445,4.6; 19 3.175,4.6; 20 1.905,4.6; 21 0.635,4.6; 22 -0.635,4.6; 23 -1.905,4.6; 24 -3.175,4.6; 25 -4.445,4.6; 26 -5.715,4.6; 27 -6.985,4.6; 28 -8.255,4.6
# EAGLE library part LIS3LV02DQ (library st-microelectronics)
MEMS INERTIAL SENSOR 3-Axis - ±2g/±6g Digital Output Low Voltage Linear Accelerometer Source: http://www.st.com/stonline/products/literature/ds/11115/lis3lv02dq.pdf

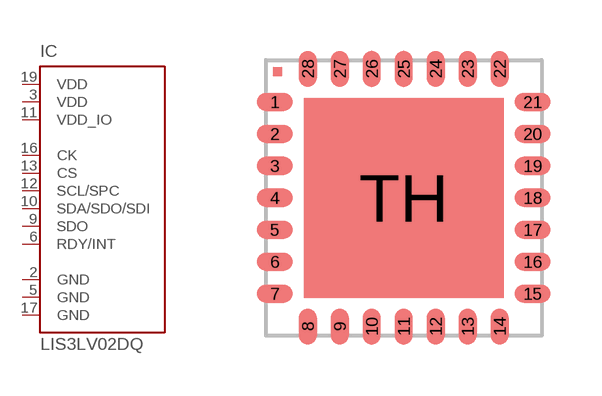
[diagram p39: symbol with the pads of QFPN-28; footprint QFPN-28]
Designator prefix IC

## LIS3LV02DQ (MF: Arrow Electronics; MPN: LIS3LV02DQ; OC_FARNELL: 1220909; OC_NEWARK: 89K0642)  [QFPN-28]
2  GND  pwr
3  VDD  pwr
5  GND  pwr
6  RDY/INT
9  SDO  out
10  SDA/SDO/SDI
11  VDD_IO  pwr
12  SCL/SPC  in
13  CS  in
16  CK  in
17  GND  pwr
19  VDD  pwr

## Footprint QFPN-28 (pad centres in mm)
QFPN-28 7x7 x 1.8mm Source: http://www.st.com/stonline/products/literature/ds/11115/lis3lv02dq.pdf
smd 0.9 x 0.45: 1 -3.225,2.4; 2 -3.225,1.6; 3 -3.225,0.8; 4 -3.225,0; 5 -3.225,-0.8; 6 -3.225,-1.6; 7 -3.225,-2.4; 15 3.225,-2.4; 16 3.225,-1.6; 17 3.225,-0.8; 18 3.225,0; 19 3.225,0.8; 20 3.225,1.6; 21 3.225,2.4
smd 0.45 x 0.9: 8 -2.4,-3.225; 9 -1.6,-3.225; 10 -0.8,-3.225; 11 0,-3.225; 12 0.8,-3.225; 13 1.6,-3.225; 14 2.4,-3.225; 22 2.4,3.225; 23 1.6,3.225; 24 0.8,3.225; 25 0,3.225; 26 -0.8,3.225; 27 -1.6,3.225; 28 -2.4,3.225
smd 5 x 5: TH 0,0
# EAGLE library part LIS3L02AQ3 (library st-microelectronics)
3-Axis - ±2g/±6g LINEAR ACCELEROMETER MEMS INERTIAL SENSOR Source: http://www.st.com/stonline/products/literature/ds/11020.pdf

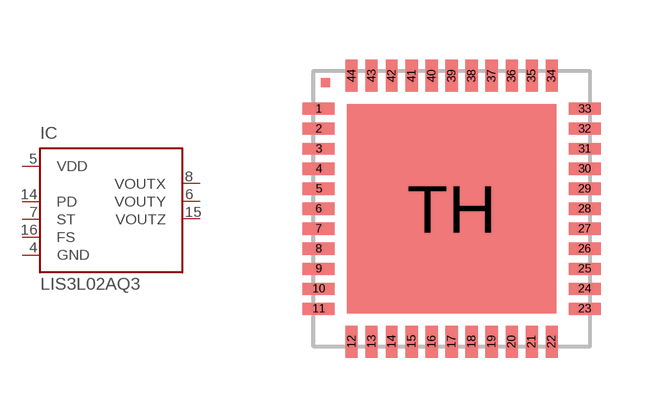
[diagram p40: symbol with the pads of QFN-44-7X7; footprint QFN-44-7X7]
Designator prefix IC

## LIS3L02AQ3 (MF: Arrow Electronics; MPN: LIS3L02AQ3; OC_FARNELL: 1467821; OC_NEWARK: 89K0645)  [QFN-44-7X7]
4  GND  pwr
5  VDD  pwr
6  VOUTY  out
7  ST  in
8  VOUTX  out
14  PD  in
15  VOUTZ  out
16  FS  in

## Footprint QFN-44-7X7 (pad centres in mm)
QFN-44 (7x7x1.8mm) Source: http://www.st.com/stonline/products/literature/ds/11020.pdf
smd 0.8 x 0.3: 1 -3.325,2.5; 2 -3.325,2; 3 -3.325,1.5; 4 -3.325,1; 5 -3.325,0.5; 6 -3.325,0; 7 -3.325,-0.5; 8 -3.325,-1; 9 -3.325,-1.5; 10 -3.325,-2; 11 -3.325,-2.5; 23 3.325,-2.5; 24 3.325,-2; 25 3.325,-1.5; 26 3.325,-1; 27 3.325,-0.5; 28 3.325,0; 29 3.325,0.5; 30 3.325,1; 31 3.325,1.5; 32 3.325,2; 33 3.325,2.5
smd 0.3 x 0.8: 12 -2.5,-3.325; 13 -2,-3.325; 14 -1.5,-3.325; 15 -1,-3.325; 16 -0.5,-3.325; 17 0,-3.325; 18 0.5,-3.325; 19 1,-3.325; 20 1.5,-3.325; 21 2,-3.325; 22 2.5,-3.325; 34 2.5,3.325; 35 2,3.325; 36 1.5,3.325; 37 1,3.325; 38 0.5,3.325; 39 0,3.325; 40 -0.5,3.325; 41 -1,3.325; 42 -1.5,3.325; 43 -2,3.325; 44 -2.5,3.325
smd 5.24 x 5.24: TH 0,0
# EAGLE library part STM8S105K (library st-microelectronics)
Access line, 16 MHz STM8S 8-bit MCU up to 32 Kbytes Flash, integrated EEPROM,10-bit ADC, timers, UART, SPI, I²C Source: Data sheet

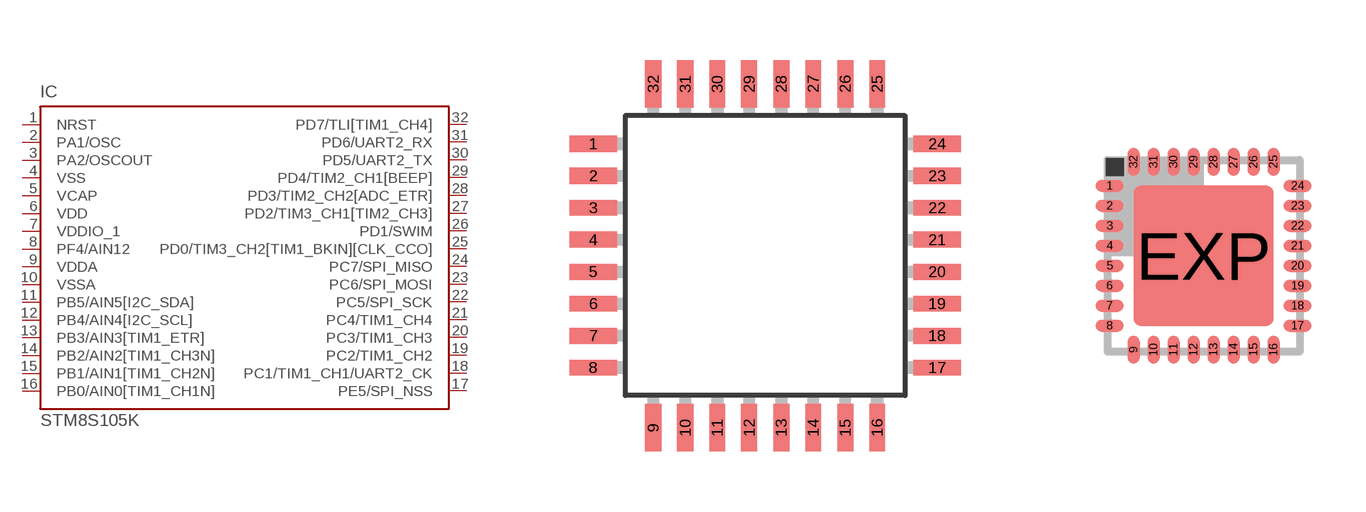
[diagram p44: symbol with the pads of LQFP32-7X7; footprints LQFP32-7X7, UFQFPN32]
Designator prefix IC

## STM8S105K4T (MPN: STM8S105K4T6C; OC_FARNELL: 1706223; OC_NEWARK: 09R6034), STM8S105K6T (MPN: STM8S105K6T6C; OC_FARNELL: 1706224; OC_NEWARK: 09R6035)  [LQFP32-7X7]
1  NRST
2  PA1/OSC
3  PA2/OSCOUT
4  VSS  pwr
5  VCAP  pwr
6  VDD  pwr
7  VDDIO_1  pwr
8  PF4/AIN12
9  VDDA  pwr
10  VSSA  pwr
11  PB5/AIN5[I2C_SDA]
12  PB4/AIN4[I2C_SCL]
13  PB3/AIN3[TIM1_ETR]
14  PB2/AIN2[TIM1_CH3N]
15  PB1/AIN1[TIM1_CH2N]
16  PB0/AIN0[TIM1_CH1N]
17  PE5/SPI_NSS
18  PC1/TIM1_CH1/UART2_CK
19  PC2/TIM1_CH2
20  PC3/TIM1_CH3
21  PC4/TIM1_CH4
22  PC5/SPI_SCK
23  PC6/SPI_MOSI
24  PC7/SPI_MISO
25  PD0/TIM3_CH2[TIM1_BKIN][CLK_CCO]
26  PD1/SWIM
27  PD2/TIM3_CH1[TIM2_CH3]
28  PD3/TIM2_CH2[ADC_ETR]
29  PD4/TIM2_CH1[BEEP]
30  PD5/UART2_TX
31  PD6/UART2_RX
32  PD7/TLI[TIM1_CH4]

## STM8S105K (MPN: STM8S105K4U6; OC_FARNELL: 1706225; OC_NEWARK: 55R6975)  [UFQFPN32]
Pads as for LQFP32-7X7

## STM8S105KU (MPN: STM8S105K6U6; OC_FARNELL: 1706225; OC_NEWARK: 09R6036)  [VFQFPN32]
Pads as for LQFP32-7X7

## Footprint LQFP32-7X7 (pad centres in mm)
LQFP-32 package 7x7 mm case, 0.8 mm lead pitch Sourced: Data sheet
smd 1.2 x 0.4: 1 -4.3,2.8; 2 -4.3,2; 3 -4.3,1.2; 4 -4.3,0.4; 5 -4.3,-0.4; 6 -4.3,-1.2; 7 -4.3,-2; 8 -4.3,-2.8; 17 4.3,-2.8; 18 4.3,-2; 19 4.3,-1.2; 20 4.3,-0.4; 21 4.3,0.4; 22 4.3,1.2; 23 4.3,2; 24 4.3,2.8
smd 0.4 x 1.2: 9 -2.8,-4.3; 10 -2,-4.3; 11 -1.2,-4.3; 12 -0.4,-4.3; 13 0.4,-4.3; 14 1.2,-4.3; 15 2,-4.3; 16 2.8,-4.3; 25 2.8,4.3; 26 2,4.3; 27 1.2,4.3; 28 0.4,4.3; 29 -0.4,4.3; 30 -1.2,4.3; 31 -2,4.3; 32 -2.8,4.3

## Footprint UFQFPN32 (pad centres in mm)
32-lead ultra thin fine pitch quad flat no-lead package (5 x 5) Source: Data sheet
smd 0.7 x 0.3: 1 -2.35,1.75; 2 -2.35,1.25; 3 -2.35,0.75; 4 -2.35,0.25; 5 -2.35,-0.25; 6 -2.35,-0.75; 7 -2.35,-1.25; 8 -2.35,-1.75; 17 2.35,-1.75; 18 2.35,-1.25; 19 2.35,-0.75; 20 2.35,-0.25; 21 2.35,0.25; 22 2.35,0.75; 23 2.35,1.25; 24 2.35,1.75
smd 0.3 x 0.7: 9 -1.75,-2.35; 10 -1.25,-2.35; 11 -0.75,-2.35; 12 -0.25,-2.35; 13 0.25,-2.35; 14 0.75,-2.35; 15 1.25,-2.35; 16 1.75,-2.35; 25 1.75,2.35; 26 1.25,2.35; 27 0.75,2.35; 28 0.25,2.35; 29 -0.25,2.35; 30 -0.75,2.35; 31 -1.25,2.35; 32 -1.75,2.35
smd 3.5 x 3.5: EXP 0,0

## Footprint VFQFPN32 (pad centres in mm)
32-lead very thin fine pitch quad flat no-lead package (5 x 5) Source: Data sheet
smd 0.7 x 0.3: 1 -2.35,1.75; 2 -2.35,1.25; 3 -2.35,0.75; 4 -2.35,0.25; 5 -2.35,-0.25; 6 -2.35,-0.75; 7 -2.35,-1.25; 8 -2.35,-1.75; 17 2.35,-1.75; 18 2.35,-1.25; 19 2.35,-0.75; 20 2.35,-0.25; 21 2.35,0.25; 22 2.35,0.75; 23 2.35,1.25; 24 2.35,1.75
smd 0.3 x 0.7: 9 -1.75,-2.35; 10 -1.25,-2.35; 11 -0.75,-2.35; 12 -0.25,-2.35; 13 0.25,-2.35; 14 0.75,-2.35; 15 1.25,-2.35; 16 1.75,-2.35; 25 1.75,2.35; 26 1.25,2.35; 27 0.75,2.35; 28 0.25,2.35; 29 -0.25,2.35; 30 -0.75,2.35; 31 -1.25,2.35; 32 -1.75,2.35
smd 3.45 x 3.45: EXP 0,0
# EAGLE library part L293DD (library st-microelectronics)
PUSH-PULL FOUR CHANNEL DRIVER WITH DIODES Source: http://www.st.com/stonline/books/pdf/docs/1330.pdf

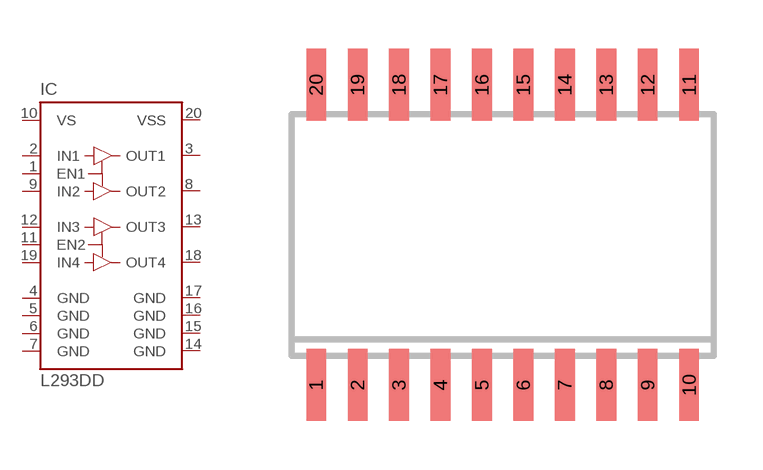
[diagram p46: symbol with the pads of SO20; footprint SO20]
Designator prefix IC

## L293DD (OC_FARNELL: unknown)  [SO20]
1  EN1  in
2  IN1  in
3  OUT1  out
4  GND  pwr
5  GND  pwr
6  GND  pwr
7  GND  pwr
8  OUT2  out
9  IN2  in
10  VS  pwr
11  EN2  in
12  IN3  in
13  OUT3  out
14  GND  pwr
15  GND  pwr
16  GND  pwr
17  GND  pwr
18  OUT4  out
19  IN4  in
20  VSS  pwr

## Footprint SO20 (pad centres in mm)
SMALL OUTLINE INTEGRATED CIRCUIT wide body 7.5 mm/JEDEC MS-013AC
smd 0.6 x 2.2: 1 -5.715,-4.6; 2 -4.445,-4.6; 3 -3.175,-4.6; 4 -1.905,-4.6; 5 -0.635,-4.6; 6 0.635,-4.6; 7 1.905,-4.6; 8 3.175,-4.6; 9 4.445,-4.6; 10 5.715,-4.6; 11 5.715,4.6; 12 4.445,4.6; 13 3.175,4.6; 14 1.905,4.6; 15 0.635,4.6; 16 -0.635,4.6; 17 -1.905,4.6; 18 -3.175,4.6; 19 -4.445,4.6; 20 -5.715,4.6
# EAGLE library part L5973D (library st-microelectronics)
2.5 A switch step down switching regulator Source: Data sheet

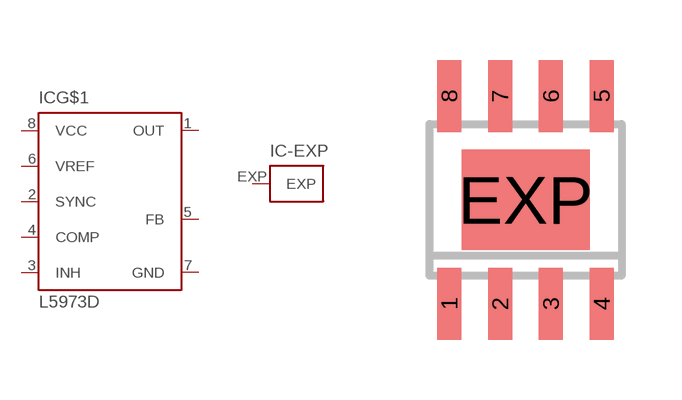
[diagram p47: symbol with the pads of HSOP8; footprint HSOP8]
Designator prefix IC; gates G$1=L5973D -EXP=EXPOSEDPAD

## L5973D (MF: STMICROELECTRONICS; MPN: L5973D; OC_FARNELL: 1077145)  [HSOP8]
1  G$1:OUT  out
2  G$1:SYNC  in
3  G$1:INH  in
4  G$1:COMP  pas
5  G$1:FB  in
6  G$1:VREF  in
7  G$1:GND  pwr
8  G$1:VCC  in
EXP  -EXP:EXP  in

## Footprint HSOP8 (pad centres in mm)
HSOP 08 (Exposed pad) Source: http://www.st.com/internet/com/TECHNICAL_RESOURCES/TECHNICAL_LITERATURE/DATASHEET/CD00002851.pdf
smd 0.6 x 1.8: 1 -1.905,-2.6; 2 -0.635,-2.6; 3 0.635,-2.6; 4 1.905,-2.6; 5 1.905,2.6; 6 0.635,2.6; 7 -0.635,2.6; 8 -1.905,2.6
smd 3.2 x 2.51: EXP 0,0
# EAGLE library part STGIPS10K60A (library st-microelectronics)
IPM, 3-phase inverter - 10 A, 600 V short-circuit rugged IGBT SLLIMM™ (small low-loss intelligent molded module) Source: Data sheet

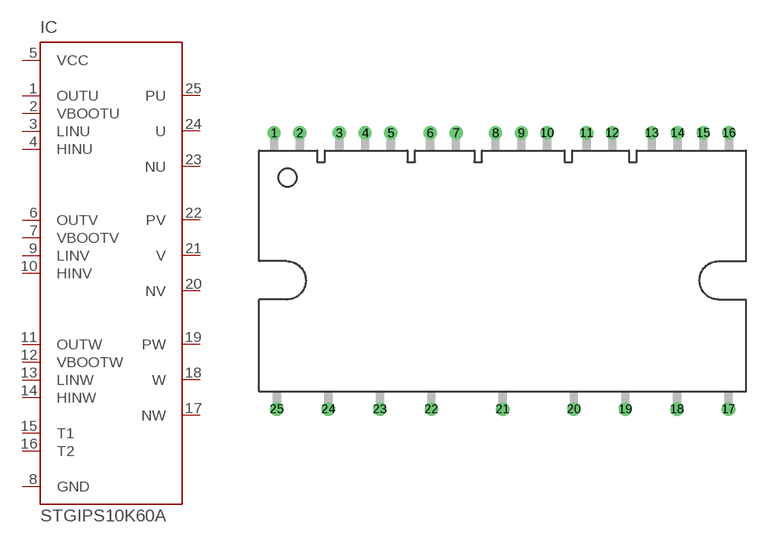
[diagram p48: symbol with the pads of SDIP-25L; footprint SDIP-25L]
Designator prefix IC

## STGIPS10K60A  [SDIP-25L]
1  OUTU  out
2  VBOOTU  out
3  LINU  in
4  HINU  in
5  VCC  pwr
6  OUTV  out
7  VBOOTV  out
8  GND  pwr
9  LINV  in
10  HINV  in
11  OUTW  out
12  VBOOTW  out
13  LINW  in
14  HINW  in
15  T1  pas
16  T2  pas
17  NW  out
18  W  out
19  PW  pwr
20  NV  out
21  V  out
22  PV  pwr
23  NU  out
24  U  out
25  PU  pwr

## Footprint SDIP-25L (pad centres in mm)
ECOPACK® Source: Data sheet
drill 0.7 pad 1.2: 1 -20.85,13.45; 2 -18.5,13.45; 3 -14.9,13.45; 4 -12.55,13.45; 5 -10.2,13.45; 6 -6.6,13.45; 7 -4.25,13.45; 8 -0.65,13.45; 9 1.7,13.45; 10 4.05,13.45; 11 7.65,13.45; 12 10,13.45; 13 13.6,13.45; 14 15.95,13.45; 15 18.3,13.45; 16 20.65,13.45; 17 20.6,-11.75; 18 15.9,-11.75; 19 11.2,-11.75; 20 6.5,-11.75; 21 0,-11.75; 22 -6.5,-11.75; 23 -11.2,-11.75; 24 -15.9,-11.75; 25 -20.6,-11.75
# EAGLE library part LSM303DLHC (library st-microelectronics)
Ultra compact high performance e-compass, 3D accelerometer and 3D magnetometer module Source: DM00027543-118326.pdf

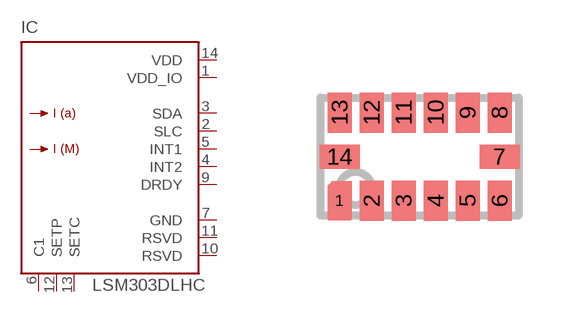
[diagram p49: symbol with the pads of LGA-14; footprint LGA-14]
Designator prefix IC

## LSM303DLHC  [LGA-14]
1  VDD_IO  pwr
2  SLC
3  SDA
4  INT2
5  INT1
6  C1  pas
7  GND  pwr
9  DRDY
10  RSVD  pas
11  RSVD  pas
12  SETP  pas
13  SETC  pas
14  VDD  pwr

## Footprint LGA-14 (pad centres in mm)
LGA 3x5x1 14L Land Grid Array Package Source: DM00027543-118326.pdf
smd 0.4 x 0.4: 1 -2,-1.1
smd 0.6 x 1: 2 -1.2,-1.1; 3 -0.4,-1.1; 4 0.4,-1.1; 5 1.2,-1.1; 6 2,-1.1; 8 2,1.1; 9 1.2,1.1; 10 0.4,1.1; 11 -0.4,1.1; 12 -1.2,1.1; 13 -2,1.1
smd 1 x 0.6: 7 2,0; 14 -2,0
